VERSION 5.8 ;
BUSBITCHARS "[]" ;
DIVIDERCHAR "/" ;
UNITS
    DATABASE MICRONS 1000 ;
END UNITS

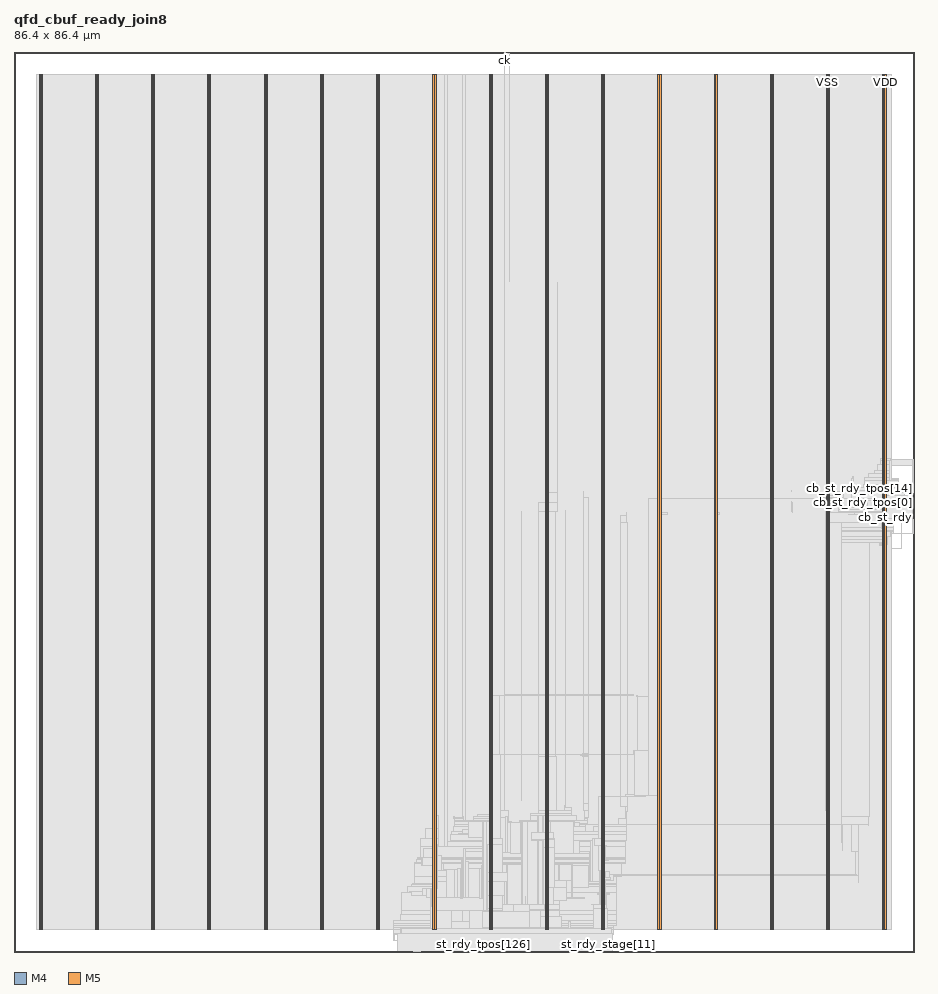
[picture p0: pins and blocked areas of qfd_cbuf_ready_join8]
MACRO qfd_cbuf_ready_join8
  FOREIGN qfd_cbuf_ready_join8 0 0 ;
  CLASS BLOCK ;
  SIZE 86.4 BY 86.4 ;
  PIN cb_fault
    DIRECTION OUTPUT ;
    USE SIGNAL ;
    PORT
      LAYER M4 ;
        RECT  86.316 41.616 86.4 41.64 ;
    END
  END cb_fault
  PIN cb_st_rdy
    DIRECTION OUTPUT ;
    USE SIGNAL ;
    PORT
      LAYER M4 ;
        RECT  86.316 41.712 86.4 41.736 ;
    END
  END cb_st_rdy
  PIN cb_st_rdy_stage[0]
    DIRECTION OUTPUT ;
    USE SIGNAL ;
    PORT
      LAYER M4 ;
        RECT  86.316 41.808 86.4 41.832 ;
    END
  END cb_st_rdy_stage[0]
  PIN cb_st_rdy_stage[1]
    DIRECTION OUTPUT ;
    USE SIGNAL ;
    PORT
      LAYER M4 ;
        RECT  86.316 41.904 86.4 41.928 ;
    END
  END cb_st_rdy_stage[1]
  PIN cb_st_rdy_stage[2]
    DIRECTION OUTPUT ;
    USE SIGNAL ;
    PORT
      LAYER M4 ;
        RECT  86.316 42 86.4 42.024 ;
    END
  END cb_st_rdy_stage[2]
  PIN cb_st_rdy_stage[3]
    DIRECTION OUTPUT ;
    USE SIGNAL ;
    PORT
      LAYER M4 ;
        RECT  86.316 42.096 86.4 42.12 ;
    END
  END cb_st_rdy_stage[3]
  PIN cb_st_rdy_stage[4]
    DIRECTION OUTPUT ;
    USE SIGNAL ;
    PORT
      LAYER M4 ;
        RECT  86.316 42.192 86.4 42.216 ;
    END
  END cb_st_rdy_stage[4]
  PIN cb_st_rdy_stage[5]
    DIRECTION OUTPUT ;
    USE SIGNAL ;
    PORT
      LAYER M4 ;
        RECT  86.316 42.288 86.4 42.312 ;
    END
  END cb_st_rdy_stage[5]
  PIN cb_st_rdy_tpos[0]
    DIRECTION OUTPUT ;
    USE SIGNAL ;
    PORT
      LAYER M4 ;
        RECT  86.316 42.384 86.4 42.408 ;
    END
  END cb_st_rdy_tpos[0]
  PIN cb_st_rdy_tpos[10]
    DIRECTION OUTPUT ;
    USE SIGNAL ;
    PORT
      LAYER M4 ;
        RECT  86.316 43.344 86.4 43.368 ;
    END
  END cb_st_rdy_tpos[10]
  PIN cb_st_rdy_tpos[11]
    DIRECTION OUTPUT ;
    USE SIGNAL ;
    PORT
      LAYER M4 ;
        RECT  86.316 43.44 86.4 43.464 ;
    END
  END cb_st_rdy_tpos[11]
  PIN cb_st_rdy_tpos[12]
    DIRECTION OUTPUT ;
    USE SIGNAL ;
    PORT
      LAYER M4 ;
        RECT  86.316 43.536 86.4 43.56 ;
    END
  END cb_st_rdy_tpos[12]
  PIN cb_st_rdy_tpos[13]
    DIRECTION OUTPUT ;
    USE SIGNAL ;
    PORT
      LAYER M4 ;
        RECT  86.316 43.632 86.4 43.656 ;
    END
  END cb_st_rdy_tpos[13]
  PIN cb_st_rdy_tpos[14]
    DIRECTION OUTPUT ;
    USE SIGNAL ;
    PORT
      LAYER M4 ;
        RECT  86.316 43.728 86.4 43.752 ;
    END
  END cb_st_rdy_tpos[14]
  PIN cb_st_rdy_tpos[15]
    DIRECTION OUTPUT ;
    USE SIGNAL ;
    PORT
      LAYER M4 ;
        RECT  86.316 43.824 86.4 43.848 ;
    END
  END cb_st_rdy_tpos[15]
  PIN cb_st_rdy_tpos[16]
    DIRECTION OUTPUT ;
    USE SIGNAL ;
    PORT
      LAYER M4 ;
        RECT  86.316 43.92 86.4 43.944 ;
    END
  END cb_st_rdy_tpos[16]
  PIN cb_st_rdy_tpos[17]
    DIRECTION OUTPUT ;
    USE SIGNAL ;
    PORT
      LAYER M4 ;
        RECT  86.316 44.016 86.4 44.04 ;
    END
  END cb_st_rdy_tpos[17]
  PIN cb_st_rdy_tpos[1]
    DIRECTION OUTPUT ;
    USE SIGNAL ;
    PORT
      LAYER M4 ;
        RECT  86.316 42.48 86.4 42.504 ;
    END
  END cb_st_rdy_tpos[1]
  PIN cb_st_rdy_tpos[2]
    DIRECTION OUTPUT ;
    USE SIGNAL ;
    PORT
      LAYER M4 ;
        RECT  86.316 42.576 86.4 42.6 ;
    END
  END cb_st_rdy_tpos[2]
  PIN cb_st_rdy_tpos[3]
    DIRECTION OUTPUT ;
    USE SIGNAL ;
    PORT
      LAYER M4 ;
        RECT  86.316 42.672 86.4 42.696 ;
    END
  END cb_st_rdy_tpos[3]
  PIN cb_st_rdy_tpos[4]
    DIRECTION OUTPUT ;
    USE SIGNAL ;
    PORT
      LAYER M4 ;
        RECT  86.316 42.768 86.4 42.792 ;
    END
  END cb_st_rdy_tpos[4]
  PIN cb_st_rdy_tpos[5]
    DIRECTION OUTPUT ;
    USE SIGNAL ;
    PORT
      LAYER M4 ;
        RECT  86.316 42.864 86.4 42.888 ;
    END
  END cb_st_rdy_tpos[5]
  PIN cb_st_rdy_tpos[6]
    DIRECTION OUTPUT ;
    USE SIGNAL ;
    PORT
      LAYER M4 ;
        RECT  86.316 42.96 86.4 42.984 ;
    END
  END cb_st_rdy_tpos[6]
  PIN cb_st_rdy_tpos[7]
    DIRECTION OUTPUT ;
    USE SIGNAL ;
    PORT
      LAYER M4 ;
        RECT  86.316 43.056 86.4 43.08 ;
    END
  END cb_st_rdy_tpos[7]
  PIN cb_st_rdy_tpos[8]
    DIRECTION OUTPUT ;
    USE SIGNAL ;
    PORT
      LAYER M4 ;
        RECT  86.316 43.152 86.4 43.176 ;
    END
  END cb_st_rdy_tpos[8]
  PIN cb_st_rdy_tpos[9]
    DIRECTION OUTPUT ;
    USE SIGNAL ;
    PORT
      LAYER M4 ;
        RECT  86.316 43.248 86.4 43.272 ;
    END
  END cb_st_rdy_tpos[9]
  PIN ck
    DIRECTION INPUT ;
    USE SIGNAL ;
    PORT
      LAYER M5 ;
        RECT  47.088 86.316 47.112 86.4 ;
    END
  END ck
  PIN fault[0]
    DIRECTION INPUT ;
    USE SIGNAL ;
    PORT
      LAYER M5 ;
        RECT  54.48 0 54.504 0.084 ;
    END
  END fault[0]
  PIN fault[1]
    DIRECTION INPUT ;
    USE SIGNAL ;
    PORT
      LAYER M5 ;
        RECT  54.576 0 54.6 0.084 ;
    END
  END fault[1]
  PIN fault[2]
    DIRECTION INPUT ;
    USE SIGNAL ;
    PORT
      LAYER M5 ;
        RECT  54.672 0 54.696 0.084 ;
    END
  END fault[2]
  PIN fault[3]
    DIRECTION INPUT ;
    USE SIGNAL ;
    PORT
      LAYER M5 ;
        RECT  54.768 0 54.792 0.084 ;
    END
  END fault[3]
  PIN fault[4]
    DIRECTION INPUT ;
    USE SIGNAL ;
    PORT
      LAYER M5 ;
        RECT  54.864 0 54.888 0.084 ;
    END
  END fault[4]
  PIN fault[5]
    DIRECTION INPUT ;
    USE SIGNAL ;
    PORT
      LAYER M5 ;
        RECT  54.96 0 54.984 0.084 ;
    END
  END fault[5]
  PIN fault[6]
    DIRECTION INPUT ;
    USE SIGNAL ;
    PORT
      LAYER M5 ;
        RECT  55.056 0 55.08 0.084 ;
    END
  END fault[6]
  PIN fault[7]
    DIRECTION INPUT ;
    USE SIGNAL ;
    PORT
      LAYER M5 ;
        RECT  55.152 0 55.176 0.084 ;
    END
  END fault[7]
  PIN rst_n
    DIRECTION INPUT ;
    USE SIGNAL ;
    PORT
      LAYER M5 ;
        RECT  47.184 86.316 47.208 86.4 ;
    END
  END rst_n
  PIN st_rdy[0]
    DIRECTION INPUT ;
    USE SIGNAL ;
    PORT
      LAYER M5 ;
        RECT  55.248 0 55.272 0.084 ;
    END
  END st_rdy[0]
  PIN st_rdy[1]
    DIRECTION INPUT ;
    USE SIGNAL ;
    PORT
      LAYER M5 ;
        RECT  55.344 0 55.368 0.084 ;
    END
  END st_rdy[1]
  PIN st_rdy[2]
    DIRECTION INPUT ;
    USE SIGNAL ;
    PORT
      LAYER M5 ;
        RECT  55.44 0 55.464 0.084 ;
    END
  END st_rdy[2]
  PIN st_rdy[3]
    DIRECTION INPUT ;
    USE SIGNAL ;
    PORT
      LAYER M5 ;
        RECT  55.536 0 55.56 0.084 ;
    END
  END st_rdy[3]
  PIN st_rdy[4]
    DIRECTION INPUT ;
    USE SIGNAL ;
    PORT
      LAYER M5 ;
        RECT  55.632 0 55.656 0.084 ;
    END
  END st_rdy[4]
  PIN st_rdy[5]
    DIRECTION INPUT ;
    USE SIGNAL ;
    PORT
      LAYER M5 ;
        RECT  55.728 0 55.752 0.084 ;
    END
  END st_rdy[5]
  PIN st_rdy[6]
    DIRECTION INPUT ;
    USE SIGNAL ;
    PORT
      LAYER M5 ;
        RECT  55.824 0 55.848 0.084 ;
    END
  END st_rdy[6]
  PIN st_rdy[7]
    DIRECTION INPUT ;
    USE SIGNAL ;
    PORT
      LAYER M5 ;
        RECT  55.92 0 55.944 0.084 ;
    END
  END st_rdy[7]
  PIN st_rdy_stage[0]
    DIRECTION INPUT ;
    USE SIGNAL ;
    PORT
      LAYER M5 ;
        RECT  56.016 0 56.04 0.084 ;
    END
  END st_rdy_stage[0]
  PIN st_rdy_stage[10]
    DIRECTION INPUT ;
    USE SIGNAL ;
    PORT
      LAYER M5 ;
        RECT  56.976 0 57 0.084 ;
    END
  END st_rdy_stage[10]
  PIN st_rdy_stage[11]
    DIRECTION INPUT ;
    USE SIGNAL ;
    PORT
      LAYER M5 ;
        RECT  57.072 0 57.096 0.084 ;
    END
  END st_rdy_stage[11]
  PIN st_rdy_stage[12]
    DIRECTION INPUT ;
    USE SIGNAL ;
    PORT
      LAYER M5 ;
        RECT  57.168 0 57.192 0.084 ;
    END
  END st_rdy_stage[12]
  PIN st_rdy_stage[13]
    DIRECTION INPUT ;
    USE SIGNAL ;
    PORT
      LAYER M5 ;
        RECT  57.264 0 57.288 0.084 ;
    END
  END st_rdy_stage[13]
  PIN st_rdy_stage[14]
    DIRECTION INPUT ;
    USE SIGNAL ;
    PORT
      LAYER M5 ;
        RECT  57.36 0 57.384 0.084 ;
    END
  END st_rdy_stage[14]
  PIN st_rdy_stage[15]
    DIRECTION INPUT ;
    USE SIGNAL ;
    PORT
      LAYER M5 ;
        RECT  57.456 0 57.48 0.084 ;
    END
  END st_rdy_stage[15]
  PIN st_rdy_stage[16]
    DIRECTION INPUT ;
    USE SIGNAL ;
    PORT
      LAYER M5 ;
        RECT  48.336 0 48.36 0.084 ;
    END
  END st_rdy_stage[16]
  PIN st_rdy_stage[17]
    DIRECTION INPUT ;
    USE SIGNAL ;
    PORT
      LAYER M5 ;
        RECT  48.432 0 48.456 0.084 ;
    END
  END st_rdy_stage[17]
  PIN st_rdy_stage[18]
    DIRECTION INPUT ;
    USE SIGNAL ;
    PORT
      LAYER M5 ;
        RECT  48.528 0 48.552 0.084 ;
    END
  END st_rdy_stage[18]
  PIN st_rdy_stage[19]
    DIRECTION INPUT ;
    USE SIGNAL ;
    PORT
      LAYER M5 ;
        RECT  48.624 0 48.648 0.084 ;
    END
  END st_rdy_stage[19]
  PIN st_rdy_stage[1]
    DIRECTION INPUT ;
    USE SIGNAL ;
    PORT
      LAYER M5 ;
        RECT  56.112 0 56.136 0.084 ;
    END
  END st_rdy_stage[1]
  PIN st_rdy_stage[20]
    DIRECTION INPUT ;
    USE SIGNAL ;
    PORT
      LAYER M5 ;
        RECT  48.72 0 48.744 0.084 ;
    END
  END st_rdy_stage[20]
  PIN st_rdy_stage[21]
    DIRECTION INPUT ;
    USE SIGNAL ;
    PORT
      LAYER M5 ;
        RECT  48.816 0 48.84 0.084 ;
    END
  END st_rdy_stage[21]
  PIN st_rdy_stage[22]
    DIRECTION INPUT ;
    USE SIGNAL ;
    PORT
      LAYER M5 ;
        RECT  48.912 0 48.936 0.084 ;
    END
  END st_rdy_stage[22]
  PIN st_rdy_stage[23]
    DIRECTION INPUT ;
    USE SIGNAL ;
    PORT
      LAYER M5 ;
        RECT  49.008 0 49.032 0.084 ;
    END
  END st_rdy_stage[23]
  PIN st_rdy_stage[24]
    DIRECTION INPUT ;
    USE SIGNAL ;
    PORT
      LAYER M5 ;
        RECT  49.104 0 49.128 0.084 ;
    END
  END st_rdy_stage[24]
  PIN st_rdy_stage[25]
    DIRECTION INPUT ;
    USE SIGNAL ;
    PORT
      LAYER M5 ;
        RECT  49.2 0 49.224 0.084 ;
    END
  END st_rdy_stage[25]
  PIN st_rdy_stage[26]
    DIRECTION INPUT ;
    USE SIGNAL ;
    PORT
      LAYER M5 ;
        RECT  49.296 0 49.32 0.084 ;
    END
  END st_rdy_stage[26]
  PIN st_rdy_stage[27]
    DIRECTION INPUT ;
    USE SIGNAL ;
    PORT
      LAYER M5 ;
        RECT  49.392 0 49.416 0.084 ;
    END
  END st_rdy_stage[27]
  PIN st_rdy_stage[28]
    DIRECTION INPUT ;
    USE SIGNAL ;
    PORT
      LAYER M5 ;
        RECT  49.488 0 49.512 0.084 ;
    END
  END st_rdy_stage[28]
  PIN st_rdy_stage[29]
    DIRECTION INPUT ;
    USE SIGNAL ;
    PORT
      LAYER M5 ;
        RECT  49.584 0 49.608 0.084 ;
    END
  END st_rdy_stage[29]
  PIN st_rdy_stage[2]
    DIRECTION INPUT ;
    USE SIGNAL ;
    PORT
      LAYER M5 ;
        RECT  56.208 0 56.232 0.084 ;
    END
  END st_rdy_stage[2]
  PIN st_rdy_stage[30]
    DIRECTION INPUT ;
    USE SIGNAL ;
    PORT
      LAYER M5 ;
        RECT  49.68 0 49.704 0.084 ;
    END
  END st_rdy_stage[30]
  PIN st_rdy_stage[31]
    DIRECTION INPUT ;
    USE SIGNAL ;
    PORT
      LAYER M5 ;
        RECT  49.776 0 49.8 0.084 ;
    END
  END st_rdy_stage[31]
  PIN st_rdy_stage[32]
    DIRECTION INPUT ;
    USE SIGNAL ;
    PORT
      LAYER M5 ;
        RECT  49.872 0 49.896 0.084 ;
    END
  END st_rdy_stage[32]
  PIN st_rdy_stage[33]
    DIRECTION INPUT ;
    USE SIGNAL ;
    PORT
      LAYER M5 ;
        RECT  49.968 0 49.992 0.084 ;
    END
  END st_rdy_stage[33]
  PIN st_rdy_stage[34]
    DIRECTION INPUT ;
    USE SIGNAL ;
    PORT
      LAYER M5 ;
        RECT  50.064 0 50.088 0.084 ;
    END
  END st_rdy_stage[34]
  PIN st_rdy_stage[35]
    DIRECTION INPUT ;
    USE SIGNAL ;
    PORT
      LAYER M5 ;
        RECT  50.16 0 50.184 0.084 ;
    END
  END st_rdy_stage[35]
  PIN st_rdy_stage[36]
    DIRECTION INPUT ;
    USE SIGNAL ;
    PORT
      LAYER M5 ;
        RECT  50.256 0 50.28 0.084 ;
    END
  END st_rdy_stage[36]
  PIN st_rdy_stage[37]
    DIRECTION INPUT ;
    USE SIGNAL ;
    PORT
      LAYER M5 ;
        RECT  50.352 0 50.376 0.084 ;
    END
  END st_rdy_stage[37]
  PIN st_rdy_stage[38]
    DIRECTION INPUT ;
    USE SIGNAL ;
    PORT
      LAYER M5 ;
        RECT  50.448 0 50.472 0.084 ;
    END
  END st_rdy_stage[38]
  PIN st_rdy_stage[39]
    DIRECTION INPUT ;
    USE SIGNAL ;
    PORT
      LAYER M5 ;
        RECT  50.544 0 50.568 0.084 ;
    END
  END st_rdy_stage[39]
  PIN st_rdy_stage[3]
    DIRECTION INPUT ;
    USE SIGNAL ;
    PORT
      LAYER M5 ;
        RECT  56.304 0 56.328 0.084 ;
    END
  END st_rdy_stage[3]
  PIN st_rdy_stage[40]
    DIRECTION INPUT ;
    USE SIGNAL ;
    PORT
      LAYER M5 ;
        RECT  50.64 0 50.664 0.084 ;
    END
  END st_rdy_stage[40]
  PIN st_rdy_stage[41]
    DIRECTION INPUT ;
    USE SIGNAL ;
    PORT
      LAYER M5 ;
        RECT  50.736 0 50.76 0.084 ;
    END
  END st_rdy_stage[41]
  PIN st_rdy_stage[42]
    DIRECTION INPUT ;
    USE SIGNAL ;
    PORT
      LAYER M5 ;
        RECT  50.832 0 50.856 0.084 ;
    END
  END st_rdy_stage[42]
  PIN st_rdy_stage[43]
    DIRECTION INPUT ;
    USE SIGNAL ;
    PORT
      LAYER M5 ;
        RECT  50.928 0 50.952 0.084 ;
    END
  END st_rdy_stage[43]
  PIN st_rdy_stage[44]
    DIRECTION INPUT ;
    USE SIGNAL ;
    PORT
      LAYER M5 ;
        RECT  51.024 0 51.048 0.084 ;
    END
  END st_rdy_stage[44]
  PIN st_rdy_stage[45]
    DIRECTION INPUT ;
    USE SIGNAL ;
    PORT
      LAYER M5 ;
        RECT  51.12 0 51.144 0.084 ;
    END
  END st_rdy_stage[45]
  PIN st_rdy_stage[46]
    DIRECTION INPUT ;
    USE SIGNAL ;
    PORT
      LAYER M5 ;
        RECT  51.216 0 51.24 0.084 ;
    END
  END st_rdy_stage[46]
  PIN st_rdy_stage[47]
    DIRECTION INPUT ;
    USE SIGNAL ;
    PORT
      LAYER M5 ;
        RECT  51.312 0 51.336 0.084 ;
    END
  END st_rdy_stage[47]
  PIN st_rdy_stage[4]
    DIRECTION INPUT ;
    USE SIGNAL ;
    PORT
      LAYER M5 ;
        RECT  56.4 0 56.424 0.084 ;
    END
  END st_rdy_stage[4]
  PIN st_rdy_stage[5]
    DIRECTION INPUT ;
    USE SIGNAL ;
    PORT
      LAYER M5 ;
        RECT  56.496 0 56.52 0.084 ;
    END
  END st_rdy_stage[5]
  PIN st_rdy_stage[6]
    DIRECTION INPUT ;
    USE SIGNAL ;
    PORT
      LAYER M5 ;
        RECT  56.592 0 56.616 0.084 ;
    END
  END st_rdy_stage[6]
  PIN st_rdy_stage[7]
    DIRECTION INPUT ;
    USE SIGNAL ;
    PORT
      LAYER M5 ;
        RECT  56.688 0 56.712 0.084 ;
    END
  END st_rdy_stage[7]
  PIN st_rdy_stage[8]
    DIRECTION INPUT ;
    USE SIGNAL ;
    PORT
      LAYER M5 ;
        RECT  56.784 0 56.808 0.084 ;
    END
  END st_rdy_stage[8]
  PIN st_rdy_stage[9]
    DIRECTION INPUT ;
    USE SIGNAL ;
    PORT
      LAYER M5 ;
        RECT  56.88 0 56.904 0.084 ;
    END
  END st_rdy_stage[9]
  PIN st_rdy_tpos[0]
    DIRECTION INPUT ;
    USE SIGNAL ;
    PORT
      LAYER M5 ;
        RECT  39.12 0 39.144 0.084 ;
    END
  END st_rdy_tpos[0]
  PIN st_rdy_tpos[100]
    DIRECTION INPUT ;
    USE SIGNAL ;
    PORT
      LAYER M5 ;
        RECT  42.576 0 42.6 0.084 ;
    END
  END st_rdy_tpos[100]
  PIN st_rdy_tpos[101]
    DIRECTION INPUT ;
    USE SIGNAL ;
    PORT
      LAYER M5 ;
        RECT  42.672 0 42.696 0.084 ;
    END
  END st_rdy_tpos[101]
  PIN st_rdy_tpos[102]
    DIRECTION INPUT ;
    USE SIGNAL ;
    PORT
      LAYER M5 ;
        RECT  42.768 0 42.792 0.084 ;
    END
  END st_rdy_tpos[102]
  PIN st_rdy_tpos[103]
    DIRECTION INPUT ;
    USE SIGNAL ;
    PORT
      LAYER M5 ;
        RECT  42.864 0 42.888 0.084 ;
    END
  END st_rdy_tpos[103]
  PIN st_rdy_tpos[104]
    DIRECTION INPUT ;
    USE SIGNAL ;
    PORT
      LAYER M5 ;
        RECT  42.96 0 42.984 0.084 ;
    END
  END st_rdy_tpos[104]
  PIN st_rdy_tpos[105]
    DIRECTION INPUT ;
    USE SIGNAL ;
    PORT
      LAYER M5 ;
        RECT  43.056 0 43.08 0.084 ;
    END
  END st_rdy_tpos[105]
  PIN st_rdy_tpos[106]
    DIRECTION INPUT ;
    USE SIGNAL ;
    PORT
      LAYER M5 ;
        RECT  43.152 0 43.176 0.084 ;
    END
  END st_rdy_tpos[106]
  PIN st_rdy_tpos[107]
    DIRECTION INPUT ;
    USE SIGNAL ;
    PORT
      LAYER M5 ;
        RECT  43.248 0 43.272 0.084 ;
    END
  END st_rdy_tpos[107]
  PIN st_rdy_tpos[108]
    DIRECTION INPUT ;
    USE SIGNAL ;
    PORT
      LAYER M5 ;
        RECT  43.344 0 43.368 0.084 ;
    END
  END st_rdy_tpos[108]
  PIN st_rdy_tpos[109]
    DIRECTION INPUT ;
    USE SIGNAL ;
    PORT
      LAYER M5 ;
        RECT  43.44 0 43.464 0.084 ;
    END
  END st_rdy_tpos[109]
  PIN st_rdy_tpos[10]
    DIRECTION INPUT ;
    USE SIGNAL ;
    PORT
      LAYER M5 ;
        RECT  40.08 0 40.104 0.084 ;
    END
  END st_rdy_tpos[10]
  PIN st_rdy_tpos[110]
    DIRECTION INPUT ;
    USE SIGNAL ;
    PORT
      LAYER M5 ;
        RECT  43.536 0 43.56 0.084 ;
    END
  END st_rdy_tpos[110]
  PIN st_rdy_tpos[111]
    DIRECTION INPUT ;
    USE SIGNAL ;
    PORT
      LAYER M5 ;
        RECT  43.632 0 43.656 0.084 ;
    END
  END st_rdy_tpos[111]
  PIN st_rdy_tpos[112]
    DIRECTION INPUT ;
    USE SIGNAL ;
    PORT
      LAYER M5 ;
        RECT  43.728 0 43.752 0.084 ;
    END
  END st_rdy_tpos[112]
  PIN st_rdy_tpos[113]
    DIRECTION INPUT ;
    USE SIGNAL ;
    PORT
      LAYER M5 ;
        RECT  43.824 0 43.848 0.084 ;
    END
  END st_rdy_tpos[113]
  PIN st_rdy_tpos[114]
    DIRECTION INPUT ;
    USE SIGNAL ;
    PORT
      LAYER M5 ;
        RECT  43.92 0 43.944 0.084 ;
    END
  END st_rdy_tpos[114]
  PIN st_rdy_tpos[115]
    DIRECTION INPUT ;
    USE SIGNAL ;
    PORT
      LAYER M5 ;
        RECT  44.016 0 44.04 0.084 ;
    END
  END st_rdy_tpos[115]
  PIN st_rdy_tpos[116]
    DIRECTION INPUT ;
    USE SIGNAL ;
    PORT
      LAYER M5 ;
        RECT  44.112 0 44.136 0.084 ;
    END
  END st_rdy_tpos[116]
  PIN st_rdy_tpos[117]
    DIRECTION INPUT ;
    USE SIGNAL ;
    PORT
      LAYER M5 ;
        RECT  44.208 0 44.232 0.084 ;
    END
  END st_rdy_tpos[117]
  PIN st_rdy_tpos[118]
    DIRECTION INPUT ;
    USE SIGNAL ;
    PORT
      LAYER M5 ;
        RECT  44.304 0 44.328 0.084 ;
    END
  END st_rdy_tpos[118]
  PIN st_rdy_tpos[119]
    DIRECTION INPUT ;
    USE SIGNAL ;
    PORT
      LAYER M5 ;
        RECT  44.4 0 44.424 0.084 ;
    END
  END st_rdy_tpos[119]
  PIN st_rdy_tpos[11]
    DIRECTION INPUT ;
    USE SIGNAL ;
    PORT
      LAYER M5 ;
        RECT  40.176 0 40.2 0.084 ;
    END
  END st_rdy_tpos[11]
  PIN st_rdy_tpos[120]
    DIRECTION INPUT ;
    USE SIGNAL ;
    PORT
      LAYER M5 ;
        RECT  44.496 0 44.52 0.084 ;
    END
  END st_rdy_tpos[120]
  PIN st_rdy_tpos[121]
    DIRECTION INPUT ;
    USE SIGNAL ;
    PORT
      LAYER M5 ;
        RECT  44.592 0 44.616 0.084 ;
    END
  END st_rdy_tpos[121]
  PIN st_rdy_tpos[122]
    DIRECTION INPUT ;
    USE SIGNAL ;
    PORT
      LAYER M5 ;
        RECT  44.688 0 44.712 0.084 ;
    END
  END st_rdy_tpos[122]
  PIN st_rdy_tpos[123]
    DIRECTION INPUT ;
    USE SIGNAL ;
    PORT
      LAYER M5 ;
        RECT  44.784 0 44.808 0.084 ;
    END
  END st_rdy_tpos[123]
  PIN st_rdy_tpos[124]
    DIRECTION INPUT ;
    USE SIGNAL ;
    PORT
      LAYER M5 ;
        RECT  44.88 0 44.904 0.084 ;
    END
  END st_rdy_tpos[124]
  PIN st_rdy_tpos[125]
    DIRECTION INPUT ;
    USE SIGNAL ;
    PORT
      LAYER M5 ;
        RECT  44.976 0 45 0.084 ;
    END
  END st_rdy_tpos[125]
  PIN st_rdy_tpos[126]
    DIRECTION INPUT ;
    USE SIGNAL ;
    PORT
      LAYER M5 ;
        RECT  45.072 0 45.096 0.084 ;
    END
  END st_rdy_tpos[126]
  PIN st_rdy_tpos[127]
    DIRECTION INPUT ;
    USE SIGNAL ;
    PORT
      LAYER M5 ;
        RECT  45.168 0 45.192 0.084 ;
    END
  END st_rdy_tpos[127]
  PIN st_rdy_tpos[128]
    DIRECTION INPUT ;
    USE SIGNAL ;
    PORT
      LAYER M5 ;
        RECT  36.816 0 36.84 0.084 ;
    END
  END st_rdy_tpos[128]
  PIN st_rdy_tpos[129]
    DIRECTION INPUT ;
    USE SIGNAL ;
    PORT
      LAYER M5 ;
        RECT  36.912 0 36.936 0.084 ;
    END
  END st_rdy_tpos[129]
  PIN st_rdy_tpos[12]
    DIRECTION INPUT ;
    USE SIGNAL ;
    PORT
      LAYER M5 ;
        RECT  40.272 0 40.296 0.084 ;
    END
  END st_rdy_tpos[12]
  PIN st_rdy_tpos[130]
    DIRECTION INPUT ;
    USE SIGNAL ;
    PORT
      LAYER M5 ;
        RECT  37.008 0 37.032 0.084 ;
    END
  END st_rdy_tpos[130]
  PIN st_rdy_tpos[131]
    DIRECTION INPUT ;
    USE SIGNAL ;
    PORT
      LAYER M5 ;
        RECT  37.104 0 37.128 0.084 ;
    END
  END st_rdy_tpos[131]
  PIN st_rdy_tpos[132]
    DIRECTION INPUT ;
    USE SIGNAL ;
    PORT
      LAYER M5 ;
        RECT  37.2 0 37.224 0.084 ;
    END
  END st_rdy_tpos[132]
  PIN st_rdy_tpos[133]
    DIRECTION INPUT ;
    USE SIGNAL ;
    PORT
      LAYER M5 ;
        RECT  37.296 0 37.32 0.084 ;
    END
  END st_rdy_tpos[133]
  PIN st_rdy_tpos[134]
    DIRECTION INPUT ;
    USE SIGNAL ;
    PORT
      LAYER M5 ;
        RECT  37.392 0 37.416 0.084 ;
    END
  END st_rdy_tpos[134]
  PIN st_rdy_tpos[135]
    DIRECTION INPUT ;
    USE SIGNAL ;
    PORT
      LAYER M5 ;
        RECT  37.488 0 37.512 0.084 ;
    END
  END st_rdy_tpos[135]
  PIN st_rdy_tpos[136]
    DIRECTION INPUT ;
    USE SIGNAL ;
    PORT
      LAYER M5 ;
        RECT  37.584 0 37.608 0.084 ;
    END
  END st_rdy_tpos[136]
  PIN st_rdy_tpos[137]
    DIRECTION INPUT ;
    USE SIGNAL ;
    PORT
      LAYER M5 ;
        RECT  37.68 0 37.704 0.084 ;
    END
  END st_rdy_tpos[137]
  PIN st_rdy_tpos[138]
    DIRECTION INPUT ;
    USE SIGNAL ;
    PORT
      LAYER M5 ;
        RECT  37.776 0 37.8 0.084 ;
    END
  END st_rdy_tpos[138]
  PIN st_rdy_tpos[139]
    DIRECTION INPUT ;
    USE SIGNAL ;
    PORT
      LAYER M5 ;
        RECT  37.872 0 37.896 0.084 ;
    END
  END st_rdy_tpos[139]
  PIN st_rdy_tpos[13]
    DIRECTION INPUT ;
    USE SIGNAL ;
    PORT
      LAYER M5 ;
        RECT  40.368 0 40.392 0.084 ;
    END
  END st_rdy_tpos[13]
  PIN st_rdy_tpos[140]
    DIRECTION INPUT ;
    USE SIGNAL ;
    PORT
      LAYER M5 ;
        RECT  37.968 0 37.992 0.084 ;
    END
  END st_rdy_tpos[140]
  PIN st_rdy_tpos[141]
    DIRECTION INPUT ;
    USE SIGNAL ;
    PORT
      LAYER M5 ;
        RECT  38.064 0 38.088 0.084 ;
    END
  END st_rdy_tpos[141]
  PIN st_rdy_tpos[142]
    DIRECTION INPUT ;
    USE SIGNAL ;
    PORT
      LAYER M5 ;
        RECT  38.16 0 38.184 0.084 ;
    END
  END st_rdy_tpos[142]
  PIN st_rdy_tpos[143]
    DIRECTION INPUT ;
    USE SIGNAL ;
    PORT
      LAYER M5 ;
        RECT  38.256 0 38.28 0.084 ;
    END
  END st_rdy_tpos[143]
  PIN st_rdy_tpos[14]
    DIRECTION INPUT ;
    USE SIGNAL ;
    PORT
      LAYER M5 ;
        RECT  40.464 0 40.488 0.084 ;
    END
  END st_rdy_tpos[14]
  PIN st_rdy_tpos[15]
    DIRECTION INPUT ;
    USE SIGNAL ;
    PORT
      LAYER M5 ;
        RECT  40.56 0 40.584 0.084 ;
    END
  END st_rdy_tpos[15]
  PIN st_rdy_tpos[16]
    DIRECTION INPUT ;
    USE SIGNAL ;
    PORT
      LAYER M5 ;
        RECT  40.656 0 40.68 0.084 ;
    END
  END st_rdy_tpos[16]
  PIN st_rdy_tpos[17]
    DIRECTION INPUT ;
    USE SIGNAL ;
    PORT
      LAYER M5 ;
        RECT  40.752 0 40.776 0.084 ;
    END
  END st_rdy_tpos[17]
  PIN st_rdy_tpos[18]
    DIRECTION INPUT ;
    USE SIGNAL ;
    PORT
      LAYER M5 ;
        RECT  40.848 0 40.872 0.084 ;
    END
  END st_rdy_tpos[18]
  PIN st_rdy_tpos[19]
    DIRECTION INPUT ;
    USE SIGNAL ;
    PORT
      LAYER M5 ;
        RECT  40.944 0 40.968 0.084 ;
    END
  END st_rdy_tpos[19]
  PIN st_rdy_tpos[1]
    DIRECTION INPUT ;
    USE SIGNAL ;
    PORT
      LAYER M5 ;
        RECT  39.216 0 39.24 0.084 ;
    END
  END st_rdy_tpos[1]
  PIN st_rdy_tpos[20]
    DIRECTION INPUT ;
    USE SIGNAL ;
    PORT
      LAYER M5 ;
        RECT  41.04 0 41.064 0.084 ;
    END
  END st_rdy_tpos[20]
  PIN st_rdy_tpos[21]
    DIRECTION INPUT ;
    USE SIGNAL ;
    PORT
      LAYER M5 ;
        RECT  41.136 0 41.16 0.084 ;
    END
  END st_rdy_tpos[21]
  PIN st_rdy_tpos[22]
    DIRECTION INPUT ;
    USE SIGNAL ;
    PORT
      LAYER M5 ;
        RECT  41.232 0 41.256 0.084 ;
    END
  END st_rdy_tpos[22]
  PIN st_rdy_tpos[23]
    DIRECTION INPUT ;
    USE SIGNAL ;
    PORT
      LAYER M5 ;
        RECT  41.328 0 41.352 0.084 ;
    END
  END st_rdy_tpos[23]
  PIN st_rdy_tpos[24]
    DIRECTION INPUT ;
    USE SIGNAL ;
    PORT
      LAYER M5 ;
        RECT  41.424 0 41.448 0.084 ;
    END
  END st_rdy_tpos[24]
  PIN st_rdy_tpos[25]
    DIRECTION INPUT ;
    USE SIGNAL ;
    PORT
      LAYER M5 ;
        RECT  41.52 0 41.544 0.084 ;
    END
  END st_rdy_tpos[25]
  PIN st_rdy_tpos[26]
    DIRECTION INPUT ;
    USE SIGNAL ;
    PORT
      LAYER M5 ;
        RECT  41.616 0 41.64 0.084 ;
    END
  END st_rdy_tpos[26]
  PIN st_rdy_tpos[27]
    DIRECTION INPUT ;
    USE SIGNAL ;
    PORT
      LAYER M5 ;
        RECT  41.712 0 41.736 0.084 ;
    END
  END st_rdy_tpos[27]
  PIN st_rdy_tpos[28]
    DIRECTION INPUT ;
    USE SIGNAL ;
    PORT
      LAYER M5 ;
        RECT  41.808 0 41.832 0.084 ;
    END
  END st_rdy_tpos[28]
  PIN st_rdy_tpos[29]
    DIRECTION INPUT ;
    USE SIGNAL ;
    PORT
      LAYER M5 ;
        RECT  41.904 0 41.928 0.084 ;
    END
  END st_rdy_tpos[29]
  PIN st_rdy_tpos[2]
    DIRECTION INPUT ;
    USE SIGNAL ;
    PORT
      LAYER M5 ;
        RECT  39.312 0 39.336 0.084 ;
    END
  END st_rdy_tpos[2]
  PIN st_rdy_tpos[30]
    DIRECTION INPUT ;
    USE SIGNAL ;
    PORT
      LAYER M5 ;
        RECT  42 0 42.024 0.084 ;
    END
  END st_rdy_tpos[30]
  PIN st_rdy_tpos[31]
    DIRECTION INPUT ;
    USE SIGNAL ;
    PORT
      LAYER M5 ;
        RECT  42.096 0 42.12 0.084 ;
    END
  END st_rdy_tpos[31]
  PIN st_rdy_tpos[32]
    DIRECTION INPUT ;
    USE SIGNAL ;
    PORT
      LAYER M5 ;
        RECT  45.264 0 45.288 0.084 ;
    END
  END st_rdy_tpos[32]
  PIN st_rdy_tpos[33]
    DIRECTION INPUT ;
    USE SIGNAL ;
    PORT
      LAYER M5 ;
        RECT  45.36 0 45.384 0.084 ;
    END
  END st_rdy_tpos[33]
  PIN st_rdy_tpos[34]
    DIRECTION INPUT ;
    USE SIGNAL ;
    PORT
      LAYER M5 ;
        RECT  45.456 0 45.48 0.084 ;
    END
  END st_rdy_tpos[34]
  PIN st_rdy_tpos[35]
    DIRECTION INPUT ;
    USE SIGNAL ;
    PORT
      LAYER M5 ;
        RECT  45.552 0 45.576 0.084 ;
    END
  END st_rdy_tpos[35]
  PIN st_rdy_tpos[36]
    DIRECTION INPUT ;
    USE SIGNAL ;
    PORT
      LAYER M5 ;
        RECT  45.648 0 45.672 0.084 ;
    END
  END st_rdy_tpos[36]
  PIN st_rdy_tpos[37]
    DIRECTION INPUT ;
    USE SIGNAL ;
    PORT
      LAYER M5 ;
        RECT  45.744 0 45.768 0.084 ;
    END
  END st_rdy_tpos[37]
  PIN st_rdy_tpos[38]
    DIRECTION INPUT ;
    USE SIGNAL ;
    PORT
      LAYER M5 ;
        RECT  45.84 0 45.864 0.084 ;
    END
  END st_rdy_tpos[38]
  PIN st_rdy_tpos[39]
    DIRECTION INPUT ;
    USE SIGNAL ;
    PORT
      LAYER M5 ;
        RECT  45.936 0 45.96 0.084 ;
    END
  END st_rdy_tpos[39]
  PIN st_rdy_tpos[3]
    DIRECTION INPUT ;
    USE SIGNAL ;
    PORT
      LAYER M5 ;
        RECT  39.408 0 39.432 0.084 ;
    END
  END st_rdy_tpos[3]
  PIN st_rdy_tpos[40]
    DIRECTION INPUT ;
    USE SIGNAL ;
    PORT
      LAYER M5 ;
        RECT  46.032 0 46.056 0.084 ;
    END
  END st_rdy_tpos[40]
  PIN st_rdy_tpos[41]
    DIRECTION INPUT ;
    USE SIGNAL ;
    PORT
      LAYER M5 ;
        RECT  46.128 0 46.152 0.084 ;
    END
  END st_rdy_tpos[41]
  PIN st_rdy_tpos[42]
    DIRECTION INPUT ;
    USE SIGNAL ;
    PORT
      LAYER M5 ;
        RECT  46.224 0 46.248 0.084 ;
    END
  END st_rdy_tpos[42]
  PIN st_rdy_tpos[43]
    DIRECTION INPUT ;
    USE SIGNAL ;
    PORT
      LAYER M5 ;
        RECT  46.32 0 46.344 0.084 ;
    END
  END st_rdy_tpos[43]
  PIN st_rdy_tpos[44]
    DIRECTION INPUT ;
    USE SIGNAL ;
    PORT
      LAYER M5 ;
        RECT  46.416 0 46.44 0.084 ;
    END
  END st_rdy_tpos[44]
  PIN st_rdy_tpos[45]
    DIRECTION INPUT ;
    USE SIGNAL ;
    PORT
      LAYER M5 ;
        RECT  46.512 0 46.536 0.084 ;
    END
  END st_rdy_tpos[45]
  PIN st_rdy_tpos[46]
    DIRECTION INPUT ;
    USE SIGNAL ;
    PORT
      LAYER M5 ;
        RECT  46.608 0 46.632 0.084 ;
    END
  END st_rdy_tpos[46]
  PIN st_rdy_tpos[47]
    DIRECTION INPUT ;
    USE SIGNAL ;
    PORT
      LAYER M5 ;
        RECT  46.704 0 46.728 0.084 ;
    END
  END st_rdy_tpos[47]
  PIN st_rdy_tpos[48]
    DIRECTION INPUT ;
    USE SIGNAL ;
    PORT
      LAYER M5 ;
        RECT  46.8 0 46.824 0.084 ;
    END
  END st_rdy_tpos[48]
  PIN st_rdy_tpos[49]
    DIRECTION INPUT ;
    USE SIGNAL ;
    PORT
      LAYER M5 ;
        RECT  46.896 0 46.92 0.084 ;
    END
  END st_rdy_tpos[49]
  PIN st_rdy_tpos[4]
    DIRECTION INPUT ;
    USE SIGNAL ;
    PORT
      LAYER M5 ;
        RECT  39.504 0 39.528 0.084 ;
    END
  END st_rdy_tpos[4]
  PIN st_rdy_tpos[50]
    DIRECTION INPUT ;
    USE SIGNAL ;
    PORT
      LAYER M5 ;
        RECT  46.992 0 47.016 0.084 ;
    END
  END st_rdy_tpos[50]
  PIN st_rdy_tpos[51]
    DIRECTION INPUT ;
    USE SIGNAL ;
    PORT
      LAYER M5 ;
        RECT  47.088 0 47.112 0.084 ;
    END
  END st_rdy_tpos[51]
  PIN st_rdy_tpos[52]
    DIRECTION INPUT ;
    USE SIGNAL ;
    PORT
      LAYER M5 ;
        RECT  47.184 0 47.208 0.084 ;
    END
  END st_rdy_tpos[52]
  PIN st_rdy_tpos[53]
    DIRECTION INPUT ;
    USE SIGNAL ;
    PORT
      LAYER M5 ;
        RECT  47.28 0 47.304 0.084 ;
    END
  END st_rdy_tpos[53]
  PIN st_rdy_tpos[54]
    DIRECTION INPUT ;
    USE SIGNAL ;
    PORT
      LAYER M5 ;
        RECT  47.376 0 47.4 0.084 ;
    END
  END st_rdy_tpos[54]
  PIN st_rdy_tpos[55]
    DIRECTION INPUT ;
    USE SIGNAL ;
    PORT
      LAYER M5 ;
        RECT  47.472 0 47.496 0.084 ;
    END
  END st_rdy_tpos[55]
  PIN st_rdy_tpos[56]
    DIRECTION INPUT ;
    USE SIGNAL ;
    PORT
      LAYER M5 ;
        RECT  47.568 0 47.592 0.084 ;
    END
  END st_rdy_tpos[56]
  PIN st_rdy_tpos[57]
    DIRECTION INPUT ;
    USE SIGNAL ;
    PORT
      LAYER M5 ;
        RECT  47.664 0 47.688 0.084 ;
    END
  END st_rdy_tpos[57]
  PIN st_rdy_tpos[58]
    DIRECTION INPUT ;
    USE SIGNAL ;
    PORT
      LAYER M5 ;
        RECT  47.76 0 47.784 0.084 ;
    END
  END st_rdy_tpos[58]
  PIN st_rdy_tpos[59]
    DIRECTION INPUT ;
    USE SIGNAL ;
    PORT
      LAYER M5 ;
        RECT  47.856 0 47.88 0.084 ;
    END
  END st_rdy_tpos[59]
  PIN st_rdy_tpos[5]
    DIRECTION INPUT ;
    USE SIGNAL ;
    PORT
      LAYER M5 ;
        RECT  39.6 0 39.624 0.084 ;
    END
  END st_rdy_tpos[5]
  PIN st_rdy_tpos[60]
    DIRECTION INPUT ;
    USE SIGNAL ;
    PORT
      LAYER M5 ;
        RECT  47.952 0 47.976 0.084 ;
    END
  END st_rdy_tpos[60]
  PIN st_rdy_tpos[61]
    DIRECTION INPUT ;
    USE SIGNAL ;
    PORT
      LAYER M5 ;
        RECT  48.048 0 48.072 0.084 ;
    END
  END st_rdy_tpos[61]
  PIN st_rdy_tpos[62]
    DIRECTION INPUT ;
    USE SIGNAL ;
    PORT
      LAYER M5 ;
        RECT  48.144 0 48.168 0.084 ;
    END
  END st_rdy_tpos[62]
  PIN st_rdy_tpos[63]
    DIRECTION INPUT ;
    USE SIGNAL ;
    PORT
      LAYER M5 ;
        RECT  48.24 0 48.264 0.084 ;
    END
  END st_rdy_tpos[63]
  PIN st_rdy_tpos[64]
    DIRECTION INPUT ;
    USE SIGNAL ;
    PORT
      LAYER M5 ;
        RECT  51.408 0 51.432 0.084 ;
    END
  END st_rdy_tpos[64]
  PIN st_rdy_tpos[65]
    DIRECTION INPUT ;
    USE SIGNAL ;
    PORT
      LAYER M5 ;
        RECT  51.504 0 51.528 0.084 ;
    END
  END st_rdy_tpos[65]
  PIN st_rdy_tpos[66]
    DIRECTION INPUT ;
    USE SIGNAL ;
    PORT
      LAYER M5 ;
        RECT  51.6 0 51.624 0.084 ;
    END
  END st_rdy_tpos[66]
  PIN st_rdy_tpos[67]
    DIRECTION INPUT ;
    USE SIGNAL ;
    PORT
      LAYER M5 ;
        RECT  51.696 0 51.72 0.084 ;
    END
  END st_rdy_tpos[67]
  PIN st_rdy_tpos[68]
    DIRECTION INPUT ;
    USE SIGNAL ;
    PORT
      LAYER M5 ;
        RECT  51.792 0 51.816 0.084 ;
    END
  END st_rdy_tpos[68]
  PIN st_rdy_tpos[69]
    DIRECTION INPUT ;
    USE SIGNAL ;
    PORT
      LAYER M5 ;
        RECT  51.888 0 51.912 0.084 ;
    END
  END st_rdy_tpos[69]
  PIN st_rdy_tpos[6]
    DIRECTION INPUT ;
    USE SIGNAL ;
    PORT
      LAYER M5 ;
        RECT  39.696 0 39.72 0.084 ;
    END
  END st_rdy_tpos[6]
  PIN st_rdy_tpos[70]
    DIRECTION INPUT ;
    USE SIGNAL ;
    PORT
      LAYER M5 ;
        RECT  51.984 0 52.008 0.084 ;
    END
  END st_rdy_tpos[70]
  PIN st_rdy_tpos[71]
    DIRECTION INPUT ;
    USE SIGNAL ;
    PORT
      LAYER M5 ;
        RECT  52.08 0 52.104 0.084 ;
    END
  END st_rdy_tpos[71]
  PIN st_rdy_tpos[72]
    DIRECTION INPUT ;
    USE SIGNAL ;
    PORT
      LAYER M5 ;
        RECT  52.176 0 52.2 0.084 ;
    END
  END st_rdy_tpos[72]
  PIN st_rdy_tpos[73]
    DIRECTION INPUT ;
    USE SIGNAL ;
    PORT
      LAYER M5 ;
        RECT  52.272 0 52.296 0.084 ;
    END
  END st_rdy_tpos[73]
  PIN st_rdy_tpos[74]
    DIRECTION INPUT ;
    USE SIGNAL ;
    PORT
      LAYER M5 ;
        RECT  52.368 0 52.392 0.084 ;
    END
  END st_rdy_tpos[74]
  PIN st_rdy_tpos[75]
    DIRECTION INPUT ;
    USE SIGNAL ;
    PORT
      LAYER M5 ;
        RECT  52.464 0 52.488 0.084 ;
    END
  END st_rdy_tpos[75]
  PIN st_rdy_tpos[76]
    DIRECTION INPUT ;
    USE SIGNAL ;
    PORT
      LAYER M5 ;
        RECT  52.56 0 52.584 0.084 ;
    END
  END st_rdy_tpos[76]
  PIN st_rdy_tpos[77]
    DIRECTION INPUT ;
    USE SIGNAL ;
    PORT
      LAYER M5 ;
        RECT  52.656 0 52.68 0.084 ;
    END
  END st_rdy_tpos[77]
  PIN st_rdy_tpos[78]
    DIRECTION INPUT ;
    USE SIGNAL ;
    PORT
      LAYER M5 ;
        RECT  52.752 0 52.776 0.084 ;
    END
  END st_rdy_tpos[78]
  PIN st_rdy_tpos[79]
    DIRECTION INPUT ;
    USE SIGNAL ;
    PORT
      LAYER M5 ;
        RECT  52.848 0 52.872 0.084 ;
    END
  END st_rdy_tpos[79]
  PIN st_rdy_tpos[7]
    DIRECTION INPUT ;
    USE SIGNAL ;
    PORT
      LAYER M5 ;
        RECT  39.792 0 39.816 0.084 ;
    END
  END st_rdy_tpos[7]
  PIN st_rdy_tpos[80]
    DIRECTION INPUT ;
    USE SIGNAL ;
    PORT
      LAYER M5 ;
        RECT  52.944 0 52.968 0.084 ;
    END
  END st_rdy_tpos[80]
  PIN st_rdy_tpos[81]
    DIRECTION INPUT ;
    USE SIGNAL ;
    PORT
      LAYER M5 ;
        RECT  53.04 0 53.064 0.084 ;
    END
  END st_rdy_tpos[81]
  PIN st_rdy_tpos[82]
    DIRECTION INPUT ;
    USE SIGNAL ;
    PORT
      LAYER M5 ;
        RECT  53.136 0 53.16 0.084 ;
    END
  END st_rdy_tpos[82]
  PIN st_rdy_tpos[83]
    DIRECTION INPUT ;
    USE SIGNAL ;
    PORT
      LAYER M5 ;
        RECT  53.232 0 53.256 0.084 ;
    END
  END st_rdy_tpos[83]
  PIN st_rdy_tpos[84]
    DIRECTION INPUT ;
    USE SIGNAL ;
    PORT
      LAYER M5 ;
        RECT  53.328 0 53.352 0.084 ;
    END
  END st_rdy_tpos[84]
  PIN st_rdy_tpos[85]
    DIRECTION INPUT ;
    USE SIGNAL ;
    PORT
      LAYER M5 ;
        RECT  53.424 0 53.448 0.084 ;
    END
  END st_rdy_tpos[85]
  PIN st_rdy_tpos[86]
    DIRECTION INPUT ;
    USE SIGNAL ;
    PORT
      LAYER M5 ;
        RECT  53.52 0 53.544 0.084 ;
    END
  END st_rdy_tpos[86]
  PIN st_rdy_tpos[87]
    DIRECTION INPUT ;
    USE SIGNAL ;
    PORT
      LAYER M5 ;
        RECT  53.616 0 53.64 0.084 ;
    END
  END st_rdy_tpos[87]
  PIN st_rdy_tpos[88]
    DIRECTION INPUT ;
    USE SIGNAL ;
    PORT
      LAYER M5 ;
        RECT  53.712 0 53.736 0.084 ;
    END
  END st_rdy_tpos[88]
  PIN st_rdy_tpos[89]
    DIRECTION INPUT ;
    USE SIGNAL ;
    PORT
      LAYER M5 ;
        RECT  53.808 0 53.832 0.084 ;
    END
  END st_rdy_tpos[89]
  PIN st_rdy_tpos[8]
    DIRECTION INPUT ;
    USE SIGNAL ;
    PORT
      LAYER M5 ;
        RECT  39.888 0 39.912 0.084 ;
    END
  END st_rdy_tpos[8]
  PIN st_rdy_tpos[90]
    DIRECTION INPUT ;
    USE SIGNAL ;
    PORT
      LAYER M5 ;
        RECT  53.904 0 53.928 0.084 ;
    END
  END st_rdy_tpos[90]
  PIN st_rdy_tpos[91]
    DIRECTION INPUT ;
    USE SIGNAL ;
    PORT
      LAYER M5 ;
        RECT  54 0 54.024 0.084 ;
    END
  END st_rdy_tpos[91]
  PIN st_rdy_tpos[92]
    DIRECTION INPUT ;
    USE SIGNAL ;
    PORT
      LAYER M5 ;
        RECT  54.096 0 54.12 0.084 ;
    END
  END st_rdy_tpos[92]
  PIN st_rdy_tpos[93]
    DIRECTION INPUT ;
    USE SIGNAL ;
    PORT
      LAYER M5 ;
        RECT  54.192 0 54.216 0.084 ;
    END
  END st_rdy_tpos[93]
  PIN st_rdy_tpos[94]
    DIRECTION INPUT ;
    USE SIGNAL ;
    PORT
      LAYER M5 ;
        RECT  54.288 0 54.312 0.084 ;
    END
  END st_rdy_tpos[94]
  PIN st_rdy_tpos[95]
    DIRECTION INPUT ;
    USE SIGNAL ;
    PORT
      LAYER M5 ;
        RECT  54.384 0 54.408 0.084 ;
    END
  END st_rdy_tpos[95]
  PIN st_rdy_tpos[96]
    DIRECTION INPUT ;
    USE SIGNAL ;
    PORT
      LAYER M5 ;
        RECT  42.192 0 42.216 0.084 ;
    END
  END st_rdy_tpos[96]
  PIN st_rdy_tpos[97]
    DIRECTION INPUT ;
    USE SIGNAL ;
    PORT
      LAYER M5 ;
        RECT  42.288 0 42.312 0.084 ;
    END
  END st_rdy_tpos[97]
  PIN st_rdy_tpos[98]
    DIRECTION INPUT ;
    USE SIGNAL ;
    PORT
      LAYER M5 ;
        RECT  42.384 0 42.408 0.084 ;
    END
  END st_rdy_tpos[98]
  PIN st_rdy_tpos[99]
    DIRECTION INPUT ;
    USE SIGNAL ;
    PORT
      LAYER M5 ;
        RECT  42.48 0 42.504 0.084 ;
    END
  END st_rdy_tpos[99]
  PIN st_rdy_tpos[9]
    DIRECTION INPUT ;
    USE SIGNAL ;
    PORT
      LAYER M5 ;
        RECT  39.984 0 40.008 0.084 ;
    END
  END st_rdy_tpos[9]
  PIN VDD
    DIRECTION INOUT ;
    USE POWER ;
    PORT
      LAYER M5 ;
        RECT  83.592 2.151 83.712 84.249 ;
        RECT  78.192 2.151 78.312 84.249 ;
        RECT  72.792 2.151 72.912 84.249 ;
        RECT  67.392 2.151 67.512 84.249 ;
        RECT  61.992 2.151 62.112 84.249 ;
        RECT  56.592 2.151 56.712 84.249 ;
        RECT  51.192 2.151 51.312 84.249 ;
        RECT  45.792 2.151 45.912 84.249 ;
        RECT  40.392 2.151 40.512 84.249 ;
        RECT  34.992 2.151 35.112 84.249 ;
        RECT  29.592 2.151 29.712 84.249 ;
        RECT  24.192 2.151 24.312 84.249 ;
        RECT  18.792 2.151 18.912 84.249 ;
        RECT  13.392 2.151 13.512 84.249 ;
        RECT  7.992 2.151 8.112 84.249 ;
        RECT  2.592 2.151 2.712 84.249 ;
    END
  END VDD
  PIN VSS
    DIRECTION INOUT ;
    USE GROUND ;
    PORT
      LAYER M5 ;
        RECT  83.4 2.137 83.52 84.263 ;
        RECT  78 2.137 78.12 84.263 ;
        RECT  72.6 2.137 72.72 84.263 ;
        RECT  67.2 2.137 67.32 84.263 ;
        RECT  61.8 2.137 61.92 84.263 ;
        RECT  56.4 2.137 56.52 84.263 ;
        RECT  51 2.137 51.12 84.263 ;
        RECT  45.6 2.137 45.72 84.263 ;
        RECT  40.2 2.137 40.32 84.263 ;
        RECT  34.8 2.137 34.92 84.263 ;
        RECT  29.4 2.137 29.52 84.263 ;
        RECT  24 2.137 24.12 84.263 ;
        RECT  18.6 2.137 18.72 84.263 ;
        RECT  13.2 2.137 13.32 84.263 ;
        RECT  7.8 2.137 7.92 84.263 ;
        RECT  2.4 2.137 2.52 84.263 ;
    END
  END VSS
  # OT_OBS_CLOSED layer=M5 d_um=1.536 added=20
  OBS
    LAYER RVTN ;
     RECT  2.16 2.16 84.24 2.295 ;
     RECT  2.16 2.565 84.24 2.835 ;
     RECT  2.16 3.105 84.24 3.375 ;
     RECT  2.16 3.645 84.24 3.915 ;
     RECT  2.16 4.185 84.24 4.455 ;
     RECT  2.16 4.725 84.24 4.995 ;
     RECT  2.16 5.265 84.24 5.535 ;
     RECT  2.16 5.805 84.24 6.075 ;
     RECT  2.16 6.345 84.24 6.615 ;
     RECT  2.16 6.885 84.24 7.155 ;
     RECT  2.16 7.425 84.24 7.695 ;
     RECT  2.16 7.965 84.24 8.235 ;
     RECT  2.16 8.505 84.24 8.775 ;
     RECT  2.16 9.045 84.24 9.315 ;
     RECT  2.16 9.585 84.24 9.855 ;
     RECT  2.16 10.125 84.24 10.395 ;
     RECT  2.16 10.665 84.24 10.935 ;
     RECT  2.16 11.205 84.24 11.475 ;
     RECT  2.16 11.745 84.24 12.015 ;
     RECT  2.16 12.285 84.24 12.555 ;
     RECT  2.16 12.825 84.24 13.095 ;
     RECT  2.16 13.365 84.24 13.635 ;
     RECT  2.16 13.905 84.24 14.175 ;
     RECT  2.16 14.445 84.24 14.715 ;
     RECT  2.16 14.985 84.24 15.255 ;
     RECT  2.16 15.525 84.24 15.795 ;
     RECT  2.16 16.065 84.24 16.335 ;
     RECT  2.16 16.605 84.24 16.875 ;
     RECT  2.16 17.145 84.24 17.415 ;
     RECT  2.16 17.685 84.24 17.955 ;
     RECT  2.16 18.225 84.24 18.495 ;
     RECT  2.16 18.765 84.24 19.035 ;
     RECT  2.16 19.305 84.24 19.575 ;
     RECT  2.16 19.845 84.24 20.115 ;
     RECT  2.16 20.385 84.24 20.655 ;
     RECT  2.16 20.925 84.24 21.195 ;
     RECT  2.16 21.465 84.24 21.735 ;
     RECT  2.16 22.005 84.24 22.275 ;
     RECT  2.16 22.545 84.24 22.815 ;
     RECT  2.16 23.085 84.24 23.355 ;
     RECT  2.16 23.625 84.24 23.895 ;
     RECT  2.16 24.165 84.24 24.435 ;
     RECT  2.16 24.705 84.24 24.975 ;
     RECT  2.16 25.245 84.24 25.515 ;
     RECT  2.16 25.785 84.24 26.055 ;
     RECT  2.16 26.325 84.24 26.595 ;
     RECT  2.16 26.865 84.24 27.135 ;
     RECT  2.16 27.405 84.24 27.675 ;
     RECT  2.16 27.945 84.24 28.215 ;
     RECT  2.16 28.485 84.24 28.755 ;
     RECT  2.16 29.025 84.24 29.295 ;
     RECT  2.16 29.565 84.24 29.835 ;
     RECT  2.16 30.105 84.24 30.375 ;
     RECT  2.16 30.645 84.24 30.915 ;
     RECT  2.16 31.185 84.24 31.455 ;
     RECT  2.16 31.725 84.24 31.995 ;
     RECT  2.16 32.265 84.24 32.535 ;
     RECT  2.16 32.805 84.24 33.075 ;
     RECT  2.16 33.345 84.24 33.615 ;
     RECT  2.16 33.885 84.24 34.155 ;
     RECT  2.16 34.425 84.24 34.695 ;
     RECT  2.16 34.965 84.24 35.235 ;
     RECT  2.16 35.505 84.24 35.775 ;
     RECT  2.16 36.045 84.24 36.315 ;
     RECT  2.16 36.585 84.24 36.855 ;
     RECT  2.16 37.125 84.24 37.395 ;
     RECT  2.16 37.665 84.24 37.935 ;
     RECT  2.16 38.205 84.24 38.475 ;
     RECT  2.16 38.745 84.24 39.015 ;
     RECT  2.16 39.285 84.24 39.555 ;
     RECT  2.16 39.825 84.24 40.095 ;
     RECT  2.16 40.365 84.24 40.635 ;
     RECT  2.16 40.905 84.24 41.175 ;
     RECT  2.16 41.445 84.24 41.715 ;
     RECT  2.16 41.985 84.24 42.255 ;
     RECT  2.16 42.525 84.24 42.795 ;
     RECT  2.16 43.065 84.24 43.335 ;
     RECT  2.16 43.605 84.24 43.875 ;
     RECT  2.16 44.145 84.24 44.415 ;
     RECT  2.16 44.685 84.24 44.955 ;
     RECT  2.16 45.225 84.24 45.495 ;
     RECT  2.16 45.765 84.24 46.035 ;
     RECT  2.16 46.305 84.24 46.575 ;
     RECT  2.16 46.845 84.24 47.115 ;
     RECT  2.16 47.385 84.24 47.655 ;
     RECT  2.16 47.925 84.24 48.195 ;
     RECT  2.16 48.465 84.24 48.735 ;
     RECT  2.16 49.005 84.24 49.275 ;
     RECT  2.16 49.545 84.24 49.815 ;
     RECT  2.16 50.085 84.24 50.355 ;
     RECT  2.16 50.625 84.24 50.895 ;
     RECT  2.16 51.165 84.24 51.435 ;
     RECT  2.16 51.705 84.24 51.975 ;
     RECT  2.16 52.245 84.24 52.515 ;
     RECT  2.16 52.785 84.24 53.055 ;
     RECT  2.16 53.325 84.24 53.595 ;
     RECT  2.16 53.865 84.24 54.135 ;
     RECT  2.16 54.405 84.24 54.675 ;
     RECT  2.16 54.945 84.24 55.215 ;
     RECT  2.16 55.485 84.24 55.755 ;
     RECT  2.16 56.025 84.24 56.295 ;
     RECT  2.16 56.565 84.24 56.835 ;
     RECT  2.16 57.105 84.24 57.375 ;
     RECT  2.16 57.645 84.24 57.915 ;
     RECT  2.16 58.185 84.24 58.455 ;
     RECT  2.16 58.725 84.24 58.995 ;
     RECT  2.16 59.265 84.24 59.535 ;
     RECT  2.16 59.805 84.24 60.075 ;
     RECT  2.16 60.345 84.24 60.615 ;
     RECT  2.16 60.885 84.24 61.155 ;
     RECT  2.16 61.425 84.24 61.695 ;
     RECT  2.16 61.965 84.24 62.235 ;
     RECT  2.16 62.505 84.24 62.775 ;
     RECT  2.16 63.045 84.24 63.315 ;
     RECT  2.16 63.585 84.24 63.855 ;
     RECT  2.16 64.125 84.24 64.395 ;
     RECT  2.16 64.665 84.24 64.935 ;
     RECT  2.16 65.205 84.24 65.475 ;
     RECT  2.16 65.745 84.24 66.015 ;
     RECT  2.16 66.285 84.24 66.555 ;
     RECT  2.16 66.825 84.24 67.095 ;
     RECT  2.16 67.365 84.24 67.635 ;
     RECT  2.16 67.905 84.24 68.175 ;
     RECT  2.16 68.445 84.24 68.715 ;
     RECT  2.16 68.985 84.24 69.255 ;
     RECT  2.16 69.525 84.24 69.795 ;
     RECT  2.16 70.065 84.24 70.335 ;
     RECT  2.16 70.605 84.24 70.875 ;
     RECT  2.16 71.145 84.24 71.415 ;
     RECT  2.16 71.685 84.24 71.955 ;
     RECT  2.16 72.225 84.24 72.495 ;
     RECT  2.16 72.765 84.24 73.035 ;
     RECT  2.16 73.305 84.24 73.575 ;
     RECT  2.16 73.845 84.24 74.115 ;
     RECT  2.16 74.385 84.24 74.655 ;
     RECT  2.16 74.925 84.24 75.195 ;
     RECT  2.16 75.465 84.24 75.735 ;
     RECT  2.16 76.005 84.24 76.275 ;
     RECT  2.16 76.545 84.24 76.815 ;
     RECT  2.16 77.085 84.24 77.355 ;
     RECT  2.16 77.625 84.24 77.895 ;
     RECT  2.16 78.165 84.24 78.435 ;
     RECT  2.16 78.705 84.24 78.975 ;
     RECT  2.16 79.245 84.24 79.515 ;
     RECT  2.16 79.785 84.24 80.055 ;
     RECT  2.16 80.325 84.24 80.595 ;
     RECT  2.16 80.865 84.24 81.135 ;
     RECT  2.16 81.405 84.24 81.675 ;
     RECT  2.16 81.945 84.24 82.215 ;
     RECT  2.16 82.485 84.24 82.755 ;
     RECT  2.16 83.025 84.24 83.295 ;
     RECT  2.16 83.565 84.24 83.835 ;
     RECT  2.16 84.105 84.24 84.24 ;
    LAYER RVTP ;
     RECT  2.16 2.295 84.24 2.565 ;
     RECT  2.16 2.835 84.24 3.105 ;
     RECT  2.16 3.375 84.24 3.645 ;
     RECT  2.16 3.915 84.24 4.185 ;
     RECT  2.16 4.455 84.24 4.725 ;
     RECT  2.16 4.995 84.24 5.265 ;
     RECT  2.16 5.535 84.24 5.805 ;
     RECT  2.16 6.075 84.24 6.345 ;
     RECT  2.16 6.615 84.24 6.885 ;
     RECT  2.16 7.155 84.24 7.425 ;
     RECT  2.16 7.695 84.24 7.965 ;
     RECT  2.16 8.235 84.24 8.505 ;
     RECT  2.16 8.775 84.24 9.045 ;
     RECT  2.16 9.315 84.24 9.585 ;
     RECT  2.16 9.855 84.24 10.125 ;
     RECT  2.16 10.395 84.24 10.665 ;
     RECT  2.16 10.935 84.24 11.205 ;
     RECT  2.16 11.475 84.24 11.745 ;
     RECT  2.16 12.015 84.24 12.285 ;
     RECT  2.16 12.555 84.24 12.825 ;
     RECT  2.16 13.095 84.24 13.365 ;
     RECT  2.16 13.635 84.24 13.905 ;
     RECT  2.16 14.175 84.24 14.445 ;
     RECT  2.16 14.715 84.24 14.985 ;
     RECT  2.16 15.255 84.24 15.525 ;
     RECT  2.16 15.795 84.24 16.065 ;
     RECT  2.16 16.335 84.24 16.605 ;
     RECT  2.16 16.875 84.24 17.145 ;
     RECT  2.16 17.415 84.24 17.685 ;
     RECT  2.16 17.955 84.24 18.225 ;
     RECT  2.16 18.495 84.24 18.765 ;
     RECT  2.16 19.035 84.24 19.305 ;
     RECT  2.16 19.575 84.24 19.845 ;
     RECT  2.16 20.115 84.24 20.385 ;
     RECT  2.16 20.655 84.24 20.925 ;
     RECT  2.16 21.195 84.24 21.465 ;
     RECT  2.16 21.735 84.24 22.005 ;
     RECT  2.16 22.275 84.24 22.545 ;
     RECT  2.16 22.815 84.24 23.085 ;
     RECT  2.16 23.355 84.24 23.625 ;
     RECT  2.16 23.895 84.24 24.165 ;
     RECT  2.16 24.435 84.24 24.705 ;
     RECT  2.16 24.975 84.24 25.245 ;
     RECT  2.16 25.515 84.24 25.785 ;
     RECT  2.16 26.055 84.24 26.325 ;
     RECT  2.16 26.595 84.24 26.865 ;
     RECT  2.16 27.135 84.24 27.405 ;
     RECT  2.16 27.675 84.24 27.945 ;
     RECT  2.16 28.215 84.24 28.485 ;
     RECT  2.16 28.755 84.24 29.025 ;
     RECT  2.16 29.295 84.24 29.565 ;
     RECT  2.16 29.835 84.24 30.105 ;
     RECT  2.16 30.375 84.24 30.645 ;
     RECT  2.16 30.915 84.24 31.185 ;
     RECT  2.16 31.455 84.24 31.725 ;
     RECT  2.16 31.995 84.24 32.265 ;
     RECT  2.16 32.535 84.24 32.805 ;
     RECT  2.16 33.075 84.24 33.345 ;
     RECT  2.16 33.615 84.24 33.885 ;
     RECT  2.16 34.155 84.24 34.425 ;
     RECT  2.16 34.695 84.24 34.965 ;
     RECT  2.16 35.235 84.24 35.505 ;
     RECT  2.16 35.775 84.24 36.045 ;
     RECT  2.16 36.315 84.24 36.585 ;
     RECT  2.16 36.855 84.24 37.125 ;
     RECT  2.16 37.395 84.24 37.665 ;
     RECT  2.16 37.935 84.24 38.205 ;
     RECT  2.16 38.475 84.24 38.745 ;
     RECT  2.16 39.015 84.24 39.285 ;
     RECT  2.16 39.555 84.24 39.825 ;
     RECT  2.16 40.095 84.24 40.365 ;
     RECT  2.16 40.635 84.24 40.905 ;
     RECT  2.16 41.175 84.24 41.445 ;
     RECT  2.16 41.715 84.24 41.985 ;
     RECT  2.16 42.255 84.24 42.525 ;
     RECT  2.16 42.795 84.24 43.065 ;
     RECT  2.16 43.335 84.24 43.605 ;
     RECT  2.16 43.875 84.24 44.145 ;
     RECT  2.16 44.415 84.24 44.685 ;
     RECT  2.16 44.955 84.24 45.225 ;
     RECT  2.16 45.495 84.24 45.765 ;
     RECT  2.16 46.035 84.24 46.305 ;
     RECT  2.16 46.575 84.24 46.845 ;
     RECT  2.16 47.115 84.24 47.385 ;
     RECT  2.16 47.655 84.24 47.925 ;
     RECT  2.16 48.195 84.24 48.465 ;
     RECT  2.16 48.735 84.24 49.005 ;
     RECT  2.16 49.275 84.24 49.545 ;
     RECT  2.16 49.815 84.24 50.085 ;
     RECT  2.16 50.355 84.24 50.625 ;
     RECT  2.16 50.895 84.24 51.165 ;
     RECT  2.16 51.435 84.24 51.705 ;
     RECT  2.16 51.975 84.24 52.245 ;
     RECT  2.16 52.515 84.24 52.785 ;
     RECT  2.16 53.055 84.24 53.325 ;
     RECT  2.16 53.595 84.24 53.865 ;
     RECT  2.16 54.135 84.24 54.405 ;
     RECT  2.16 54.675 84.24 54.945 ;
     RECT  2.16 55.215 84.24 55.485 ;
     RECT  2.16 55.755 84.24 56.025 ;
     RECT  2.16 56.295 84.24 56.565 ;
     RECT  2.16 56.835 84.24 57.105 ;
     RECT  2.16 57.375 84.24 57.645 ;
     RECT  2.16 57.915 84.24 58.185 ;
     RECT  2.16 58.455 84.24 58.725 ;
     RECT  2.16 58.995 84.24 59.265 ;
     RECT  2.16 59.535 84.24 59.805 ;
     RECT  2.16 60.075 84.24 60.345 ;
     RECT  2.16 60.615 84.24 60.885 ;
     RECT  2.16 61.155 84.24 61.425 ;
     RECT  2.16 61.695 84.24 61.965 ;
     RECT  2.16 62.235 84.24 62.505 ;
     RECT  2.16 62.775 84.24 63.045 ;
     RECT  2.16 63.315 84.24 63.585 ;
     RECT  2.16 63.855 84.24 64.125 ;
     RECT  2.16 64.395 84.24 64.665 ;
     RECT  2.16 64.935 84.24 65.205 ;
     RECT  2.16 65.475 84.24 65.745 ;
     RECT  2.16 66.015 84.24 66.285 ;
     RECT  2.16 66.555 84.24 66.825 ;
     RECT  2.16 67.095 84.24 67.365 ;
     RECT  2.16 67.635 84.24 67.905 ;
     RECT  2.16 68.175 84.24 68.445 ;
     RECT  2.16 68.715 84.24 68.985 ;
     RECT  2.16 69.255 84.24 69.525 ;
     RECT  2.16 69.795 84.24 70.065 ;
     RECT  2.16 70.335 84.24 70.605 ;
     RECT  2.16 70.875 84.24 71.145 ;
     RECT  2.16 71.415 84.24 71.685 ;
     RECT  2.16 71.955 84.24 72.225 ;
     RECT  2.16 72.495 84.24 72.765 ;
     RECT  2.16 73.035 84.24 73.305 ;
     RECT  2.16 73.575 84.24 73.845 ;
     RECT  2.16 74.115 84.24 74.385 ;
     RECT  2.16 74.655 84.24 74.925 ;
     RECT  2.16 75.195 84.24 75.465 ;
     RECT  2.16 75.735 84.24 76.005 ;
     RECT  2.16 76.275 84.24 76.545 ;
     RECT  2.16 76.815 84.24 77.085 ;
     RECT  2.16 77.355 84.24 77.625 ;
     RECT  2.16 77.895 84.24 78.165 ;
     RECT  2.16 78.435 84.24 78.705 ;
     RECT  2.16 78.975 84.24 79.245 ;
     RECT  2.16 79.515 84.24 79.785 ;
     RECT  2.16 80.055 84.24 80.325 ;
     RECT  2.16 80.595 84.24 80.865 ;
     RECT  2.16 81.135 84.24 81.405 ;
     RECT  2.16 81.675 84.24 81.945 ;
     RECT  2.16 82.215 84.24 82.485 ;
     RECT  2.16 82.755 84.24 83.025 ;
     RECT  2.16 83.295 84.24 83.565 ;
     RECT  2.16 83.835 84.24 84.105 ;
    LAYER M1 ;
     RECT  2.16 2.151 84.24 84.249 ;
    LAYER M2 ;
     RECT  2.16 2.151 41.323 84.249 ;
     RECT  41.323 2.106 41.639 84.249 ;
     RECT  41.639 2.151 43.051 84.249 ;
     RECT  43.051 2.106 43.367 84.249 ;
     RECT  43.367 2.151 84.24 84.249 ;
     RECT  84.24 45.198 84.371 45.414 ;
     RECT  84.24 42.534 84.407 44.244 ;
     RECT  84.24 40.176 84.443 40.734 ;
     RECT  84.407 42.606 84.443 44.244 ;
     RECT  84.371 45.396 84.911 45.414 ;
     RECT  84.24 38.718 85.199 38.736 ;
     RECT  84.443 42.606 85.451 44.064 ;
     RECT  85.451 42.606 85.487 43.254 ;
     RECT  85.451 44.046 85.487 44.064 ;
     RECT  84.24 46.746 86.279 47.304 ;
     RECT  84.443 40.176 86.315 40.194 ;
     RECT  85.487 42.732 86.315 42.75 ;
     RECT  86.279 47.196 86.315 47.304 ;
     RECT  86.287 43.731 86.387 43.749 ;
     RECT  86.315 47.196 86.387 47.214 ;
    LAYER M3 ;
     RECT  51.3 0.091 51.318 0.523 ;
     RECT  39.384 0.091 39.402 0.571 ;
     RECT  43.74 0.523 43.758 0.571 ;
     RECT  44.496 0.523 44.514 0.571 ;
     RECT  50.652 0.523 51.318 0.571 ;
     RECT  57.06 0.523 57.078 0.571 ;
     RECT  47.916 0.523 47.934 1.099 ;
     RECT  57.06 0.571 57.258 1.099 ;
     RECT  39.384 0.571 39.942 1.147 ;
     RECT  41.616 0.091 41.634 1.147 ;
     RECT  49.392 0.571 49.41 1.147 ;
     RECT  44.496 0.571 45.09 1.579 ;
     RECT  41.616 1.147 42.246 1.627 ;
     RECT  39.384 1.147 40.662 1.675 ;
     RECT  41.616 1.627 42.57 1.675 ;
     RECT  47.916 1.099 47.97 1.675 ;
     RECT  48.852 1.147 49.41 1.675 ;
     RECT  53.712 0.571 53.73 1.675 ;
     RECT  36.468 1.099 36.486 1.723 ;
     RECT  39.384 1.675 42.57 1.723 ;
     RECT  43.344 0.571 43.758 1.723 ;
     RECT  44.496 1.579 45.342 1.723 ;
     RECT  46.836 1.147 46.854 1.723 ;
     RECT  47.916 1.675 49.41 1.723 ;
     RECT  50.256 0.571 51.318 1.723 ;
     RECT  53.604 1.675 53.73 1.723 ;
     RECT  55.44 0.571 55.458 1.723 ;
     RECT  56.592 1.099 57.258 1.723 ;
     RECT  36.468 1.723 37.926 1.771 ;
     RECT  36.468 1.771 38.07 2.203 ;
     RECT  38.952 1.723 57.546 2.203 ;
     RECT  36.468 2.203 57.546 2.371 ;
     RECT  2.415 2.143 2.505 2.413 ;
     RECT  7.815 2.143 7.905 2.413 ;
     RECT  13.215 2.143 13.305 2.413 ;
     RECT  18.615 2.143 18.705 2.413 ;
     RECT  24.015 2.143 24.105 2.413 ;
     RECT  29.415 2.143 29.505 2.413 ;
     RECT  34.815 2.143 34.905 2.413 ;
     RECT  61.815 2.143 61.905 2.413 ;
     RECT  67.215 2.143 67.305 2.413 ;
     RECT  72.615 2.143 72.705 2.413 ;
     RECT  78.015 2.143 78.105 2.413 ;
     RECT  83.415 2.143 83.505 2.413 ;
     RECT  36.468 2.371 57.582 2.569 ;
     RECT  36.468 2.569 57.87 2.759 ;
     RECT  36.468 2.759 57.834 3.065 ;
     RECT  37.116 3.065 57.834 3.605 ;
     RECT  37.224 3.605 57.834 3.955 ;
     RECT  37.224 3.955 57.87 5.729 ;
     RECT  37.8 5.729 57.87 6.269 ;
     RECT  38.124 6.269 57.87 6.449 ;
     RECT  38.268 6.449 57.87 6.575 ;
     RECT  38.448 6.575 57.87 7.231 ;
     RECT  81.036 6.691 81.054 7.387 ;
     RECT  38.448 7.231 58.302 8.509 ;
     RECT  38.448 8.509 58.734 8.573 ;
     RECT  38.664 8.573 58.734 8.879 ;
     RECT  38.736 8.879 58.734 8.969 ;
     RECT  38.772 8.969 58.734 9.113 ;
     RECT  80.82 7.387 81.054 9.661 ;
     RECT  38.988 9.113 58.734 10.157 ;
     RECT  79.524 9.751 79.542 10.471 ;
     RECT  41.616 10.157 58.734 10.625 ;
     RECT  41.868 10.625 58.734 10.741 ;
     RECT  38.988 10.157 40.77 10.931 ;
     RECT  79.452 10.471 79.542 11.011 ;
     RECT  41.868 10.741 58.842 11.273 ;
     RECT  42.012 11.273 58.842 11.543 ;
     RECT  39.528 10.931 40.77 11.813 ;
     RECT  55.584 11.543 58.842 12.011 ;
     RECT  42.192 11.543 54.846 12.083 ;
     RECT  56.196 12.011 58.842 12.209 ;
     RECT  80.388 9.661 81.054 12.217 ;
     RECT  82.008 12.181 82.026 12.217 ;
     RECT  79.452 11.011 79.578 12.235 ;
     RECT  80.388 12.217 82.026 12.235 ;
     RECT  42.336 12.083 54.846 12.245 ;
     RECT  56.196 12.209 56.862 12.281 ;
     RECT  48.564 12.245 54.846 12.361 ;
     RECT  42.336 12.245 47.79 12.515 ;
     RECT  48.564 12.361 55.062 12.587 ;
     RECT  48.564 12.587 48.582 12.623 ;
     RECT  42.336 12.515 47.466 12.659 ;
     RECT  54.72 12.587 55.062 12.785 ;
     RECT  44.1 12.659 47.466 12.821 ;
     RECT  42.336 12.659 43.11 12.829 ;
     RECT  57.996 12.209 58.842 12.857 ;
     RECT  56.196 12.281 56.697 12.865 ;
     RECT  42.228 12.829 43.11 12.893 ;
     RECT  54.792 12.785 55.062 12.901 ;
     RECT  79.452 12.235 82.026 12.991 ;
     RECT  42.228 12.893 42.246 13.019 ;
     RECT  43.092 12.893 43.11 13.019 ;
     RECT  44.1 12.821 45.897 13.019 ;
     RECT  56.124 12.865 56.697 13.019 ;
     RECT  40.215 11.813 40.77 13.091 ;
     RECT  49.608 12.587 53.982 13.091 ;
     RECT  44.46 13.019 45.897 13.163 ;
     RECT  45.18 13.163 45.897 13.199 ;
     RECT  49.608 13.091 53.478 13.289 ;
     RECT  58.716 12.857 58.842 13.441 ;
     RECT  46.62 12.821 47.466 13.559 ;
     RECT  50.328 13.289 53.478 13.559 ;
     RECT  54.792 12.901 55.17 13.567 ;
     RECT  78.015 2.413 78.297 13.567 ;
     RECT  52.884 13.559 53.478 13.829 ;
     RECT  58.716 13.441 58.878 13.981 ;
     RECT  52.884 13.829 52.938 14.099 ;
     RECT  54.684 13.567 55.17 14.251 ;
     RECT  60.552 14.953 60.57 15.005 ;
     RECT  60.912 15.061 60.93 15.179 ;
     RECT  54.648 14.251 55.17 18.769 ;
     RECT  50.328 13.559 52.11 18.797 ;
     RECT  54.576 18.769 55.17 18.859 ;
     RECT  54.36 18.859 55.17 18.959 ;
     RECT  54.576 18.959 55.17 19.067 ;
     RECT  59.796 24.523 59.814 24.629 ;
     RECT  58.176 13.981 58.878 24.664 ;
     RECT  58.176 24.664 59.49 24.701 ;
     RECT  83.415 2.413 83.697 38.713 ;
     RECT  83.415 38.713 83.79 39.055 ;
     RECT  83.124 39.055 83.79 39.091 ;
     RECT  83.124 39.091 83.826 39.181 ;
     RECT  79.452 12.991 82.134 39.289 ;
     RECT  83.124 39.181 83.862 39.289 ;
     RECT  79.452 39.289 83.862 39.631 ;
     RECT  79.452 39.631 83.898 39.865 ;
     RECT  79.452 39.865 84.114 40.405 ;
     RECT  79.452 40.405 84.366 40.441 ;
     RECT  79.452 40.441 84.402 40.711 ;
     RECT  77.904 13.567 78.297 41.251 ;
     RECT  79.452 40.711 84.438 41.251 ;
     RECT  58.176 24.701 58.878 41.279 ;
     RECT  58.176 41.279 58.842 41.909 ;
     RECT  86.292 40.171 86.31 41.933 ;
     RECT  61.815 2.413 62.097 41.989 ;
     RECT  67.215 2.413 67.497 41.989 ;
     RECT  58.824 41.909 58.842 42.179 ;
     RECT  61.815 41.989 62.73 42.179 ;
     RECT  67.215 41.989 67.698 42.179 ;
     RECT  77.904 41.251 84.438 42.179 ;
     RECT  85.176 38.713 85.194 42.221 ;
     RECT  48.672 14.521 48.69 42.251 ;
     RECT  50.328 18.797 51.966 42.295 ;
     RECT  79.128 42.179 84.438 42.317 ;
     RECT  74.736 42.223 74.754 42.331 ;
     RECT  52.92 14.099 52.938 42.359 ;
     RECT  79.128 42.317 84.402 42.449 ;
     RECT  79.128 42.449 81.954 42.719 ;
     RECT  86.292 42.727 86.31 42.797 ;
     RECT  85.464 42.571 85.482 43.051 ;
     RECT  77.904 42.179 78.39 43.069 ;
     RECT  79.128 42.719 79.398 43.069 ;
     RECT  46.62 13.559 47.106 43.133 ;
     RECT  82.836 42.449 84.402 43.147 ;
     RECT  85.428 43.051 85.482 43.147 ;
     RECT  50.328 42.295 52.146 43.169 ;
     RECT  74.664 42.331 74.754 43.169 ;
     RECT  82.836 43.147 85.482 43.231 ;
     RECT  74.664 43.169 74.682 43.259 ;
     RECT  77.904 43.069 79.398 43.303 ;
     RECT  80.388 42.719 81.954 43.339 ;
     RECT  82.728 43.231 85.482 43.339 ;
     RECT  77.724 43.303 79.398 43.528 ;
     RECT  80.388 43.339 85.482 43.528 ;
     RECT  77.724 43.528 85.482 43.565 ;
     RECT  77.724 43.565 79.614 43.609 ;
     RECT  46.62 43.133 46.638 43.637 ;
     RECT  54.648 19.067 55.17 43.673 ;
     RECT  86.292 43.72 86.31 43.726 ;
     RECT  77.58 43.609 79.614 43.799 ;
     RECT  77.724 43.799 79.614 43.871 ;
     RECT  86.292 43.726 86.382 44.011 ;
     RECT  78.015 43.871 79.614 44.069 ;
     RECT  80.388 43.565 85.482 44.069 ;
     RECT  51.015 43.169 52.146 44.105 ;
     RECT  78.015 44.069 79.398 44.177 ;
     RECT  54.648 43.673 54.666 44.249 ;
     RECT  74.664 44.221 74.682 44.339 ;
     RECT  80.388 44.069 84.906 44.339 ;
     RECT  79.38 44.177 79.398 44.411 ;
     RECT  80.424 44.339 84.906 44.609 ;
     RECT  80.424 44.609 80.766 44.717 ;
     RECT  81.54 44.609 84.906 44.879 ;
     RECT  81.612 44.879 84.906 45.221 ;
     RECT  80.424 44.717 80.55 45.419 ;
     RECT  84.888 45.221 84.906 45.419 ;
     RECT  81.612 45.221 84.042 45.527 ;
     RECT  80.532 45.419 80.55 45.689 ;
     RECT  82.044 45.527 84.042 45.959 ;
     RECT  82.584 45.959 84.042 46.265 ;
     RECT  82.908 46.265 84.042 46.769 ;
     RECT  86.256 44.011 86.382 46.769 ;
     RECT  83.16 46.769 84.042 47.155 ;
     RECT  86.292 46.769 86.382 47.219 ;
     RECT  86.292 47.219 86.31 47.309 ;
     RECT  83.16 47.155 84.114 47.345 ;
     RECT  83.415 47.345 84.114 47.381 ;
     RECT  52.128 44.105 52.146 64.319 ;
     RECT  2.415 2.413 2.697 83.987 ;
     RECT  7.815 2.413 8.097 83.987 ;
     RECT  13.215 2.413 13.497 83.987 ;
     RECT  18.615 2.413 18.897 83.987 ;
     RECT  24.015 2.413 24.297 83.987 ;
     RECT  29.415 2.413 29.697 83.987 ;
     RECT  34.815 2.413 35.097 83.987 ;
     RECT  40.215 13.091 40.497 83.987 ;
     RECT  45.615 13.199 45.897 83.987 ;
     RECT  51.015 44.105 51.297 83.987 ;
     RECT  56.415 13.019 56.697 83.987 ;
     RECT  61.815 42.179 62.097 83.987 ;
     RECT  67.215 42.179 67.497 83.987 ;
     RECT  72.615 2.413 72.897 83.987 ;
     RECT  78.015 44.177 78.297 83.987 ;
     RECT  83.415 47.381 83.697 83.987 ;
     RECT  2.415 83.987 2.505 84.257 ;
     RECT  7.815 83.987 7.905 84.257 ;
     RECT  13.215 83.987 13.305 84.257 ;
     RECT  18.615 83.987 18.705 84.257 ;
     RECT  24.015 83.987 24.105 84.257 ;
     RECT  29.415 83.987 29.505 84.257 ;
     RECT  34.815 83.987 34.905 84.257 ;
     RECT  40.215 83.987 40.305 84.257 ;
     RECT  45.615 83.987 45.705 84.257 ;
     RECT  51.015 83.987 51.105 84.257 ;
     RECT  56.415 83.987 56.505 84.257 ;
     RECT  61.815 83.987 61.905 84.257 ;
     RECT  67.215 83.987 67.305 84.257 ;
     RECT  72.615 83.987 72.705 84.257 ;
     RECT  78.015 83.987 78.105 84.257 ;
     RECT  83.415 83.987 83.505 84.257 ;
     RECT  47.556 64.363 47.574 86.285 ;
    LAYER M4 ;
     RECT  2.408 2.148 2.512 84.252 ;
     RECT  2.512 2.418 2.704 83.982 ;
     RECT  7.808 2.148 7.912 84.252 ;
     RECT  7.912 2.418 8.104 83.982 ;
     RECT  13.208 2.148 13.312 84.252 ;
     RECT  13.312 2.418 13.504 83.982 ;
     RECT  18.608 2.148 18.712 84.252 ;
     RECT  18.712 2.418 18.904 83.982 ;
     RECT  24.008 2.148 24.112 84.252 ;
     RECT  24.112 2.418 24.304 83.982 ;
     RECT  29.408 2.148 29.512 84.252 ;
     RECT  29.512 2.418 29.704 83.982 ;
     RECT  34.808 2.148 34.912 84.252 ;
     RECT  34.912 2.418 35.104 83.982 ;
     RECT  36.457 1.104 36.805 1.128 ;
     RECT  36.805 1.104 36.889 1.752 ;
     RECT  36.889 1.104 37.043 1.8 ;
     RECT  37.043 1.728 37.105 1.8 ;
     RECT  38.005 5.808 38.149 5.832 ;
     RECT  37.105 1.728 38.195 2.28 ;
     RECT  38.195 1.728 39.164 2.232 ;
     RECT  38.761 9.072 39.164 9.096 ;
     RECT  38.149 5.472 39.229 5.832 ;
     RECT  39.164 8.352 39.301 9.096 ;
     RECT  39.373 0.096 39.457 0.12 ;
     RECT  39.229 5.472 39.589 6.12 ;
     RECT  39.869 0.144 39.953 0.6 ;
     RECT  39.589 5.28 40.021 6.12 ;
     RECT  40.021 4.368 40.069 6.12 ;
     RECT  39.164 1.728 40.208 2.28 ;
     RECT  40.069 3.984 40.208 6.12 ;
     RECT  39.301 8.352 40.208 9.912 ;
     RECT  39.953 0.144 40.307 0.168 ;
     RECT  40.208 1.728 40.312 84.252 ;
     RECT  40.312 1.728 40.453 83.982 ;
     RECT  40.453 1.152 40.504 83.982 ;
     RECT  40.504 7.872 40.643 10.296 ;
     RECT  40.504 1.152 40.673 2.28 ;
     RECT  40.643 7.872 40.673 9.912 ;
     RECT  40.673 7.872 41.069 9.24 ;
     RECT  40.673 1.68 41.075 2.28 ;
     RECT  41.069 7.872 41.249 8.52 ;
     RECT  40.504 5.28 41.497 6.792 ;
     RECT  41.249 7.872 41.497 7.896 ;
     RECT  41.605 0.096 41.689 0.12 ;
     RECT  41.075 1.728 42.145 2.28 ;
     RECT  42.145 1.728 42.173 2.904 ;
     RECT  42.173 1.152 42.257 2.904 ;
     RECT  41.497 5.28 42.289 7.896 ;
     RECT  42.289 5.232 42.541 7.896 ;
     RECT  42.257 1.632 42.803 2.904 ;
     RECT  42.541 5.232 42.901 7.992 ;
     RECT  42.901 5.136 42.973 7.992 ;
     RECT  42.901 9.024 42.973 9.048 ;
     RECT  42.973 5.136 43.013 9.048 ;
     RECT  42.803 1.728 43.049 2.904 ;
     RECT  42.685 11.376 43.081 11.4 ;
     RECT  43.013 5.232 43.153 9.048 ;
     RECT  43.153 5.232 43.301 9.96 ;
     RECT  43.333 0.576 43.417 0.6 ;
     RECT  43.301 5.232 43.589 8.712 ;
     RECT  43.081 11.376 43.657 11.784 ;
     RECT  41.989 3.984 43.805 4.008 ;
     RECT  43.589 5.232 44.665 7.992 ;
     RECT  43.049 1.728 44.737 2.28 ;
     RECT  44.665 5.136 44.881 7.992 ;
     RECT  44.737 1.728 44.917 2.904 ;
     RECT  44.881 5.136 44.953 8.28 ;
     RECT  43.301 9.696 44.953 9.96 ;
     RECT  43.657 10.992 44.953 12.504 ;
     RECT  44.917 1.68 45.025 2.904 ;
     RECT  43.729 0.528 45.061 0.552 ;
     RECT  44.945 3.984 45.097 4.008 ;
     RECT  44.953 5.136 45.097 12.504 ;
     RECT  45.061 0.528 45.145 0.6 ;
     RECT  45.025 1.632 45.313 2.904 ;
     RECT  45.313 1.584 45.397 2.904 ;
     RECT  45.097 3.984 45.397 12.504 ;
     RECT  45.397 1.584 45.608 12.504 ;
     RECT  45.608 1.584 45.712 84.252 ;
     RECT  45.712 1.584 45.904 83.982 ;
     RECT  45.397 0.144 46.067 0.36 ;
     RECT  45.904 1.584 46.067 8.376 ;
     RECT  46.067 0.144 46.106 0.168 ;
     RECT  46.067 1.584 46.115 3.336 ;
     RECT  46.067 4.416 46.117 8.376 ;
     RECT  46.115 1.584 46.781 2.76 ;
     RECT  46.781 1.152 46.865 2.76 ;
     RECT  46.865 1.728 46.883 2.76 ;
     RECT  45.904 9.6 47.221 12.888 ;
     RECT  46.117 4.56 47.293 8.376 ;
     RECT  46.883 1.728 47.315 2.28 ;
     RECT  47.221 9.6 47.333 12.984 ;
     RECT  47.293 3.84 47.411 8.376 ;
     RECT  47.173 86.256 47.585 86.28 ;
     RECT  47.333 9.6 47.689 12.408 ;
     RECT  47.905 0.528 47.941 0.552 ;
     RECT  47.315 1.728 47.941 1.896 ;
     RECT  47.941 0.528 48.179 1.896 ;
     RECT  48.179 1.104 48.371 1.896 ;
     RECT  47.689 9.456 48.661 12.408 ;
     RECT  48.371 1.152 48.697 1.896 ;
     RECT  47.411 4.56 48.733 8.376 ;
     RECT  48.661 9.456 48.733 12.504 ;
     RECT  48.733 4.56 48.841 12.504 ;
     RECT  48.697 1.152 49.043 2.28 ;
     RECT  49.043 1.68 49.139 2.28 ;
     RECT  48.841 4.56 49.273 12.552 ;
     RECT  49.139 1.728 49.993 2.28 ;
     RECT  49.273 3.984 50.281 12.552 ;
     RECT  49.381 0.576 50.329 0.6 ;
     RECT  50.281 3.984 50.353 13.032 ;
     RECT  49.993 1.728 50.78 2.952 ;
     RECT  50.353 3.984 50.78 13.128 ;
     RECT  50.78 1.728 50.785 13.128 ;
     RECT  50.785 1.632 51.008 13.128 ;
     RECT  45.904 18.96 51.008 18.984 ;
     RECT  47.077 24.672 51.008 24.696 ;
     RECT  51.008 1.632 51.059 84.252 ;
     RECT  51.059 1.728 51.112 84.252 ;
     RECT  50.641 0.528 51.251 0.552 ;
     RECT  51.112 1.728 51.304 83.982 ;
     RECT  51.289 0.096 51.373 0.12 ;
     RECT  51.304 1.728 51.509 12.504 ;
     RECT  51.509 1.728 51.635 8.424 ;
     RECT  51.635 3.36 52.307 8.424 ;
     RECT  52.307 4.56 52.403 8.424 ;
     RECT  52.403 4.992 52.409 8.424 ;
     RECT  52.307 3.36 52.595 3.384 ;
     RECT  52.409 4.992 53.075 5.208 ;
     RECT  51.635 1.728 53.233 2.28 ;
     RECT  53.233 1.728 53.417 2.904 ;
     RECT  53.075 5.184 53.485 5.208 ;
     RECT  52.409 6.24 53.485 8.424 ;
     RECT  53.417 1.728 53.564 2.28 ;
     RECT  53.485 5.184 53.569 8.424 ;
     RECT  53.569 6.24 53.633 8.424 ;
     RECT  53.564 1.68 53.651 2.28 ;
     RECT  51.509 9.504 53.705 12.504 ;
     RECT  53.701 0.576 53.785 0.6 ;
     RECT  53.705 12.048 53.813 12.504 ;
     RECT  53.705 9.504 54.245 10.728 ;
     RECT  53.813 12.048 54.245 12.408 ;
     RECT  54.245 12.048 54.281 12.264 ;
     RECT  51.304 18.96 54.349 18.984 ;
     RECT  53.569 5.184 54.749 5.208 ;
     RECT  54.349 18.864 54.785 18.984 ;
     RECT  53.633 6.24 55.181 8.328 ;
     RECT  55.181 6.816 55.249 8.328 ;
     RECT  54.245 9.504 55.249 9.624 ;
     RECT  55.249 6.816 55.357 9.624 ;
     RECT  54.245 10.704 55.357 10.728 ;
     RECT  55.429 0.576 55.513 0.6 ;
     RECT  55.357 6.816 55.573 10.728 ;
     RECT  55.429 4.56 55.813 4.584 ;
     RECT  55.813 3.984 56.213 4.584 ;
     RECT  56.005 5.568 56.213 5.592 ;
     RECT  56.213 3.984 56.245 5.592 ;
     RECT  55.573 6.816 56.245 10.872 ;
     RECT  56.245 3.984 56.365 10.872 ;
     RECT  53.651 1.728 56.408 2.28 ;
     RECT  56.365 3.984 56.408 10.92 ;
     RECT  54.281 12.24 56.408 12.264 ;
     RECT  56.101 14.928 56.408 14.952 ;
     RECT  54.785 18.96 56.408 18.984 ;
     RECT  51.304 24.672 56.408 24.696 ;
     RECT  56.245 0.144 56.485 0.168 ;
     RECT  56.408 1.728 56.485 84.252 ;
     RECT  56.485 0.144 56.512 84.252 ;
     RECT  56.512 0.144 56.621 83.982 ;
     RECT  56.621 1.728 56.704 83.982 ;
     RECT  56.704 8.784 56.765 10.2 ;
     RECT  56.704 4.128 56.86 5.688 ;
     RECT  56.621 0.144 56.867 0.6 ;
     RECT  56.86 4.128 56.867 5.592 ;
     RECT  56.765 10.176 56.873 10.2 ;
     RECT  56.867 0.192 56.963 0.6 ;
     RECT  56.867 4.128 56.963 4.152 ;
     RECT  56.765 8.784 57.089 8.808 ;
     RECT  56.963 0.528 57.107 0.6 ;
     RECT  56.704 6.864 57.125 7.752 ;
     RECT  56.867 5.568 57.161 5.592 ;
     RECT  57.107 0.576 57.313 0.6 ;
     RECT  56.704 1.728 57.395 2.28 ;
     RECT  57.125 6.864 57.521 7.416 ;
     RECT  57.395 1.728 57.557 1.752 ;
     RECT  56.704 14.928 58.705 14.952 ;
     RECT  58.705 14.928 58.745 15.096 ;
     RECT  56.704 24.672 59.501 24.696 ;
     RECT  56.704 18.96 59.509 18.984 ;
     RECT  59.509 18.96 59.555 19.368 ;
     RECT  59.555 19.344 59.843 19.368 ;
     RECT  59.785 24.528 59.869 24.552 ;
     RECT  58.745 14.976 60.581 15.096 ;
     RECT  57.521 7.392 61.808 7.416 ;
     RECT  56.704 12.24 61.808 12.264 ;
     RECT  60.581 15.072 61.808 15.096 ;
     RECT  60.901 43.536 61.808 43.56 ;
     RECT  61.808 2.148 61.912 84.252 ;
     RECT  61.912 2.418 62.104 83.982 ;
     RECT  62.104 7.392 67.208 7.416 ;
     RECT  62.104 12.24 67.208 12.264 ;
     RECT  62.104 43.536 67.208 43.56 ;
     RECT  67.208 2.148 67.312 84.252 ;
     RECT  67.312 2.418 67.504 83.982 ;
     RECT  67.504 7.392 72.608 7.416 ;
     RECT  67.504 12.24 72.608 12.264 ;
     RECT  67.504 43.536 72.608 43.56 ;
     RECT  72.608 2.148 72.712 84.252 ;
     RECT  72.712 2.418 72.904 83.982 ;
     RECT  72.904 7.392 78.008 7.416 ;
     RECT  72.904 12.24 78.008 12.264 ;
     RECT  72.904 43.536 78.008 43.56 ;
     RECT  78.008 2.148 78.112 84.252 ;
     RECT  78.112 2.418 78.304 83.982 ;
     RECT  78.304 43.536 79.697 43.56 ;
     RECT  78.304 12.24 80.309 12.264 ;
     RECT  80.089 42 80.701 42.024 ;
     RECT  78.304 7.392 80.849 7.416 ;
     RECT  80.701 42 81.241 42.168 ;
     RECT  81.241 42 81.281 42.216 ;
     RECT  81.281 42.048 81.821 42.216 ;
     RECT  81.821 42.192 81.929 42.216 ;
     RECT  83.269 40.704 83.408 40.728 ;
     RECT  83.257 41.952 83.408 41.976 ;
     RECT  83.408 2.148 83.512 84.252 ;
     RECT  83.512 2.418 83.704 83.982 ;
     RECT  83.704 41.616 86.245 43.848 ;
     RECT  86.245 41.616 86.364 44.04 ;
    LAYER M5 ;
     RECT  36.816 0.016 57.48 1.763 ;
     RECT  36.912 1.763 57.384 1.811 ;
     RECT  2.4 2.137 2.52 2.151 ;
     RECT  7.8 2.137 7.92 2.151 ;
     RECT  13.2 2.137 13.32 2.151 ;
     RECT  18.6 2.137 18.72 2.151 ;
     RECT  24 2.137 24.12 2.151 ;
     RECT  29.4 2.137 29.52 2.151 ;
     RECT  34.8 2.137 34.92 2.151 ;
     RECT  61.8 2.137 61.92 2.151 ;
     RECT  67.2 2.137 67.32 2.151 ;
     RECT  72.6 2.137 72.72 2.151 ;
     RECT  78 2.137 78.12 2.151 ;
     RECT  83.4 2.137 83.52 2.151 ;
     RECT  37.2 1.811 57.384 2.243 ;
     RECT  37.2 2.243 38.184 2.291 ;
     RECT  39.216 2.243 57.384 2.291 ;
     RECT  44.976 2.291 52.584 2.339 ;
     RECT  42 2.291 43.752 2.915 ;
     RECT  50.544 2.339 52.584 3.395 ;
     RECT  44.976 2.339 49.512 3.875 ;
     RECT  42 2.915 42.024 4.019 ;
     RECT  43.056 2.915 43.752 4.019 ;
     RECT  44.976 3.875 46.92 4.019 ;
     RECT  50.544 3.395 52.392 4.019 ;
     RECT  50.64 4.019 52.392 4.067 ;
     RECT  55.632 2.291 56.952 4.163 ;
     RECT  45.456 4.019 46.92 4.211 ;
     RECT  40.032 2.291 40.512 4.403 ;
     RECT  47.952 3.875 49.512 4.595 ;
     RECT  50.88 4.067 52.392 4.595 ;
     RECT  55.632 4.163 56.856 4.595 ;
     RECT  56.256 4.595 56.856 4.691 ;
     RECT  49.056 4.595 49.08 5.315 ;
     RECT  45.504 4.211 46.92 5.461 ;
     RECT  56.4 4.691 56.808 5.699 ;
     RECT  53.04 4.981 53.064 5.701 ;
     RECT  40.2 4.403 40.512 6.085 ;
     RECT  56.4 5.699 56.712 6.181 ;
     RECT  51 4.595 51.816 6.229 ;
     RECT  45.504 5.461 47.112 6.757 ;
     RECT  53.04 5.701 53.544 6.899 ;
     RECT  56.256 6.181 56.712 6.949 ;
     RECT  53.52 6.899 53.544 7.091 ;
     RECT  56.256 6.949 57.24 7.139 ;
     RECT  45.504 6.757 47.4 7.619 ;
     RECT  56.256 7.139 56.808 7.763 ;
     RECT  56.256 7.763 56.712 7.813 ;
     RECT  40.2 6.085 40.632 8.341 ;
     RECT  39.216 8.341 40.632 9.107 ;
     RECT  51 6.229 51.864 10.069 ;
     RECT  56.112 7.813 56.712 10.213 ;
     RECT  40.2 9.107 40.632 10.307 ;
     RECT  45.504 7.619 46.872 10.355 ;
     RECT  50.832 10.069 51.864 10.787 ;
     RECT  45.6 10.355 46.872 10.883 ;
     RECT  51 10.787 51.864 10.883 ;
     RECT  55.68 10.213 56.712 10.883 ;
     RECT  49.68 10.693 49.704 11.459 ;
     RECT  51 10.883 51.816 11.507 ;
     RECT  56.112 10.883 56.712 14.963 ;
     RECT  61.8 2.151 62.112 15.061 ;
     RECT  45.6 10.883 46.68 18.995 ;
     RECT  59.52 14.965 59.544 19.333 ;
     RECT  59.52 19.333 59.832 19.379 ;
     RECT  59.808 19.379 59.832 24.563 ;
     RECT  83.4 2.151 83.712 40.693 ;
     RECT  83.28 40.693 83.712 41.987 ;
     RECT  60.912 15.061 62.112 43.571 ;
     RECT  2.4 2.151 2.712 84.249 ;
     RECT  7.8 2.151 8.112 84.249 ;
     RECT  13.2 2.151 13.512 84.249 ;
     RECT  18.6 2.151 18.912 84.249 ;
     RECT  24 2.151 24.312 84.249 ;
     RECT  29.4 2.151 29.712 84.249 ;
     RECT  34.8 2.151 35.112 84.249 ;
     RECT  40.2 10.307 40.512 84.249 ;
     RECT  45.6 18.995 45.912 84.249 ;
     RECT  51 11.507 51.312 84.249 ;
     RECT  56.4 14.963 56.712 84.249 ;
     RECT  61.8 43.571 62.112 84.249 ;
     RECT  67.2 2.151 67.512 84.249 ;
     RECT  72.6 2.151 72.912 84.249 ;
     RECT  78 2.151 78.312 84.249 ;
     RECT  83.4 41.987 83.712 84.249 ;
     RECT  2.4 84.249 2.52 84.263 ;
     RECT  7.8 84.249 7.92 84.263 ;
     RECT  13.2 84.249 13.32 84.263 ;
     RECT  18.6 84.249 18.72 84.263 ;
     RECT  24 84.249 24.12 84.263 ;
     RECT  29.4 84.249 29.52 84.263 ;
     RECT  34.8 84.249 34.92 84.263 ;
     RECT  40.2 84.249 40.32 84.263 ;
     RECT  45.6 84.249 45.72 84.263 ;
     RECT  51 84.249 51.12 84.263 ;
     RECT  56.4 84.249 56.52 84.263 ;
     RECT  61.8 84.249 61.92 84.263 ;
     RECT  67.2 84.249 67.32 84.263 ;
     RECT  72.6 84.249 72.72 84.263 ;
     RECT  78 84.249 78.12 84.263 ;
     RECT  83.4 84.249 83.52 84.263 ;
     RECT  47.088 24.661 47.112 86.245 ;
     RECT  47.088 86.245 47.208 86.352 ;
     RECT  38.184 2.243 39.216 2.291 ;
     RECT  40.512 2.291 42 4.019 ;
     RECT  43.752 2.291 44.976 4.019 ;
     RECT  49.512 2.339 50.544 4.019 ;
     RECT  42.024 2.915 43.056 4.019 ;
     RECT  46.92 3.875 47.952 4.595 ;
     RECT  49.512 4.019 50.64 4.067 ;
     RECT  49.512 4.067 50.88 4.595 ;
     RECT  46.92 4.595 47.112 5.461 ;
     RECT  51.816 4.595 52.392 4.981 ;
     RECT  56.256 4.691 56.4 6.181 ;
     RECT  51.816 4.981 53.04 6.229 ;
     RECT  56.712 5.699 56.808 6.949 ;
     RECT  51.864 6.229 53.04 6.899 ;
     RECT  49.704 10.693 50.832 10.787 ;
     RECT  49.704 10.787 51 11.459 ;
     RECT  59.544 15.061 60.912 19.333 ;
     RECT  59.832 19.333 60.912 24.563 ;
     RECT  45.912 24.661 47.088 84.249 ;
     RECT  45.72 84.249 47.088 84.263 ;
  END
END qfd_cbuf_ready_join8
END LIBRARY
